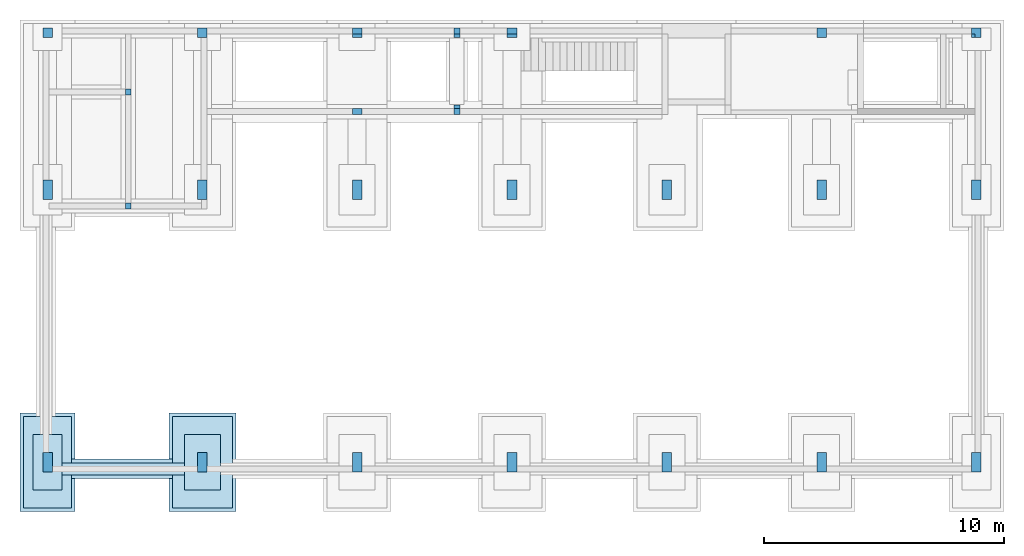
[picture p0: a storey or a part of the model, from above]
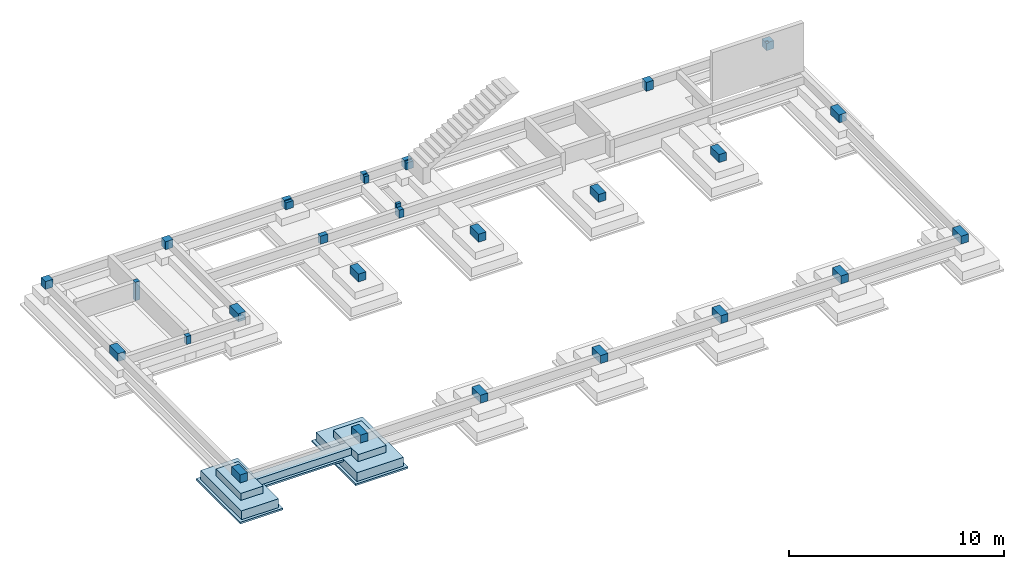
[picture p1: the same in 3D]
Properties of the parts of a building model (IFC2X3), part 1 of 2

# File
Description: ViewDefinition [CoordinationView_V2.0]
File name: Numer projektu
Time: 2022-04-22T09:22:17
Written by: The EXPRESS Data Manager Version 5.02.0100.07 : 28 Aug 2013
Made in: 22.0.2.392 - Exporter 22.0.2.392 - Zastępczy Interfejs Użytkownika 22.0.2.392
Comment: STEP Physical File produced by: The EXPRESS Data Manager Version 5.02.0100.07 : 28 Aug 2013 * Module: EDMstepFileFactory/EDMstandAlone * Creation date: Fri Apr 22 09:22:17 2022 * Host: DESKTOP-EC0AMMV * Database: C:\Users\User\AppData\Local\Temp\685c151b-a8d0-49df-8c9f-2104059c286f\b235b335-c000-40b2-a10a-5bbda26b3f6b\ifc * Database version: 5507 * Database creation date: Fri Apr 22 09:21:30 2022 * Schema: IFC2X3 * Model: DataRepository.ifc * Model creation date: Fri Apr 22 09:21:31 2022 * Header model: DataRepository.ifc_HeaderModel * Header model creation date: Fri Apr 22 09:21:31 2022 * EDMuser: sdai-user * EDMgroup: sdai-group * License ID and type: 5605 : Permanent license. Expiry date: * EDMstepFileFactory options: 020000

# IfcProject, Numer projektu
LongName: Nazwa projektu; Phase: Stan projektu

# IfcSite, Default
RefLatitude: 52, 14, 59, 999999; RefLongitude: 20, 59, 59, 999999; RefElevation: 0 cm

# IfcBuilding
Pset_BuildingCommon - NumberOfStoreys: 6

# IfcBuildingStorey: Poziom:8 mm - początek (6)
Name | LongName | Elevation (cm)
Poziom Fundament -1,15 | Poziom Fundament -1,15 | -115
Poziom 0K -0,10 | Poziom 0K -0,10 | -10
Poziom 0 A +/-0,00 | Poziom 0 A +/-0,00 | 3.3857e-11
Poziom Antresola +2,90 | Poziom Antresola +2,90 | 290
Poziom 1K +5,45 | Poziom 1K +5,45 | 545
Poziom 2K +9,70 | Poziom 2K +9,70 | 970

# IfcBeam: Beton-belka prostokątna:BELKA 190x25, Beton-belka prostokątna:BELKA 190x25:542715
In: Poziom 2K +9,70
Type - Pset_BeamCommon - LoadBearing: yes; IsExternal: no
Material: _Beton C30/37
Pset_BeamCommon - Slope: 0 deg; Reference: BELKA 190x25; Span: 854.762 cm
Pset_QuantityTakeOff - Reference: BELKA 190x25; sets with these values: 2

# IfcBeam: Beton-belka prostokątna:BELKA 21x34, Beton-belka prostokątna:BELKA 21x34:641071
In: Poziom 1K +5,45
Type - Pset_BeamCommon - LoadBearing: yes; IsExternal: no
Material: _Beton C30/37
Pset_BeamCommon - Slope: 0 deg; Reference: BELKA 21x34; Span: 297 cm
Pset_QuantityTakeOff - Reference: BELKA 21x34; sets with these values: 2

# IfcBeam: Beton-belka prostokątna:BELKA 25x40 (2)
In: Poziom 1K +5,45
Type - Pset_BeamCommon - LoadBearing: yes; IsExternal: no
Material: _Beton C30/37
Pset_BeamCommon - Slope: 0 deg; Reference: BELKA 25x40; Span: 622.5 cm
Pset_QuantityTakeOff - Reference: BELKA 25x40; sets with these values: 2
Name (Beton-belka prostokątna:BELKA 25x40:...)
481778
486543

# IfcBeam: Beton-belka prostokątna:BELKA 40x30 (2)
In: Poziom 1K +5,45
Type - PredefinedType: BEAM; Material: _Beton C30/37
Type - Pset_BeamCommon - LoadBearing: yes; IsExternal: no
Pset_BeamCommon - Slope: 0 deg; Reference: BELKA 40x30
Pset_QuantityTakeOff - Reference: BELKA 40x30; sets with these values: 2
Name (Beton-belka prostokątna:BELKA 40x30:...) | Span (cm)
435028 | 1850
448956 | 665

# IfcBeam: Beton-belka prostokątna:BELKA 40x30 (13)
In: Poziom 1K +5,45
Type - Pset_BeamCommon - LoadBearing: yes; IsExternal: no
Material: _Beton C30/37
Pset_BeamCommon - Slope: 0 deg; Reference: BELKA 40x30
Pset_QuantityTakeOff - Reference: BELKA 40x30; sets with these values: 2
Name (Beton-belka prostokątna:BELKA 40x30:...) | Span (cm)
434826 | 350
447698 | 305
447766 | 1195
448347 | 625
448529 | 645
448852 | 427.5
449135 | 625
596459 | 605
597098 | 605
597211 | 605
597310 | 605
597330 | 605
597412 | 800

# IfcBeam: Beton-belka prostokątna:BELKA 40x45 (2)
In: Poziom 0K -0,10
Type - Pset_BeamCommon - LoadBearing: yes; IsExternal: no
Material: _Beton C30/37
Pset_BeamCommon - Slope: 0 deg; Reference: BELKA 40x45
Pset_QuantityTakeOff - Reference: BELKA 40x45; sets with these values: 2
Name (Beton-belka prostokątna:BELKA 40x45:...) | Span (cm)
433060 | 123.77
660178 | 531.23

# IfcBeam: Beton-belka prostokątna:BELKA ŻELBETOWA 10x25 (3)
In: Poziom Antresola +2,90
Type - Pset_BeamCommon - LoadBearing: yes; IsExternal: no
Material: _Beton C30/37
Pset_BeamCommon - Slope: 0 deg; Reference: BELKA ŻELBETOWA 10x25
Pset_QuantityTakeOff - Reference: BELKA ŻELBETOWA 10x25; sets with these values: 2
Name (Beton-belka prostokątna:BELKA ŻELBETOWA 10x25:...) | Span (cm)
526152 | 331
534554 | 463.5
534562 | 331

# IfcBeam: Beton-belka prostokątna:BELKA ŻELBETOWA 35x25, Beton-belka prostokątna:BELKA ŻELBETOWA 35x25:540405
In: Poziom Antresola +2,90
Type - Pset_BeamCommon - LoadBearing: yes; IsExternal: no
Material: _Beton C30/37
Pset_BeamCommon - Slope: 0 deg; Reference: BELKA ŻELBETOWA 35x25; Span: 242.456 cm
Pset_QuantityTakeOff - Reference: BELKA ŻELBETOWA 35x25; sets with these values: 2

# IfcBeam: Beton-belka prostokątna:Belka żelbetowa 40x155cm (9)
In: Poziom 0K -0,10
Type - Pset_BeamCommon - LoadBearing: yes; IsExternal: no
Material: _Beton C30/37
Pset_BeamCommon - Slope: 0 deg; Reference: Belka żelbetowa 40x155cm
Pset_QuantityTakeOff - Reference: Belka żelbetowa 40x155cm; sets with these values: 2
Name (Beton-belka prostokątna:Belka żelbetowa 40x155cm:...) | Span (cm)
432161 | 1215
432658 | 1113.75
437235 | 655
438517 | 625
439012 | 645
439243 | 645
439613 | 645
439765 | 645
439812 | 625

# IfcBeam: Beton-belka prostokątna:Belka żelbetowa 40x60cm (6)
In: Poziom 0K -0,10
Type - Pset_BeamCommon - LoadBearing: yes; IsExternal: no
Material: _Beton C30/37
Pset_BeamCommon - Slope: 0 deg; Reference: Belka żelbetowa 40x60cm
Pset_QuantityTakeOff - Reference: Belka żelbetowa 40x60cm; sets with these values: 2
Name (Beton-belka prostokątna:Belka żelbetowa 40x60cm:...) | Span (cm)
481795 | 605
481805 | 606
481807 | 606
481809 | 606
481814 | 605
481832 | 605

# IfcBeam: Beton-belka prostokątna:Belka żelbetowa 40x65 cm (5)
In: Poziom 0K -0,10
Type - PredefinedType: BEAM; Material: _Beton, C25/30
Type - Pset_BeamCommon - LoadBearing: yes; IsExternal: no
Pset_BeamCommon - Slope: 0 deg; Reference: Belka żelbetowa 40x65 cm
Pset_QuantityTakeOff - Reference: Belka żelbetowa 40x65 cm; sets with these values: 2
Name (Beton-belka prostokątna:Belka żelbetowa 40x65 cm:...) | Span (cm)
422655 | 1175
432189 | 1175
432206 | 1175
432730 | 1176
481820 | 1176

# IfcBeam: Beton-belka prostokątna:wieniec 10x15 (8)
In: Poziom 2K +9,70
Type - Pset_BeamCommon - LoadBearing: yes; IsExternal: no
Material: _Beton C30/37
Pset_BeamCommon - Slope: 0 deg; Reference: wieniec 10x15
Pset_QuantityTakeOff - Reference: wieniec 10x15; sets with these values: 2
Name (Beton-belka prostokątna:wieniec 10x15:...) | Span (cm)
623789 | 80.0001
623798 | 80.0001
623804 | 250
623812 | 250
635637 | 115
635639 | 120.002
635653 | 115
635659 | 120.002

# IfcBeam: Beton-belka prostokątna:wieniec 25x25 (18)
Type - PredefinedType: BEAM; Material: _Beton C30/37
Type - Pset_BeamCommon - LoadBearing: yes; IsExternal: no
Pset_BeamCommon - Slope: 0 deg; Reference: wieniec 25x25
Pset_QuantityTakeOff - Reference: wieniec 25x25; sets with these values: 2
Name (Beton-belka prostokątna:wieniec 25x25:...) | In | Span (cm)
443020 | Poziom 0K -0,10 | 1024
443519 | Poziom 0K -0,10 | 330
443610 | Poziom 0K -0,10 | 605
443694 | Poziom 0K -0,10 | 605
443745 | Poziom 0K -0,10 | 605
443802 | Poziom 0K -0,10 | 1041.51
451564 | Poziom 1K +5,45 | 1001.8
452412 | Poziom 1K +5,45 | 605
452460 | Poziom 1K +5,45 | 605
452469 | Poziom 1K +5,45 | 605
452478 | Poziom 1K +5,45 | 605
452495 | Poziom 1K +5,45 | 605
452915 | Poziom 1K +5,45 | 1001.8
564734 | Poziom 0 A +/-0,00 | 329
565840 | Poziom 0 A +/-0,00 | 6
565847 | Poziom Antresola +2,90 | 2.5
565852 | Poziom 0 A +/-0,00 | 273
601474 | Poziom 1K +5,45 | 273

# IfcBeam: C:C160 (6)
In: Poziom Antresola +2,90
Type - Pset_BeamCommon - LoadBearing: yes; IsExternal: no
Material: Stal konstrukcyjna - S235
Pset_BeamCommon - Slope: 0 deg; Reference: C160
Pset_QuantityTakeOff - Reference: C160; sets with these values: 2
Name (C:C160:...) | Span (cm)
565581 | 285.5
565635 | 632.87
565638 | 1275.61
567058 | 427.36
567066 | 291.16
574626 | 167.49

# IfcBeam: C:C200 (6)
Type - Pset_BeamCommon - LoadBearing: yes; IsExternal: no
Material: Stal konstrukcyjna - S235
Pset_BeamCommon - Reference: C200
Pset_QuantityTakeOff - Reference: C200; sets with these values: 2
Name (C:C200:...) | In | Slope (deg) | Span (cm)
692104 | Poziom 2K +9,70 | 0 | 262
692492 | Poziom 2K +9,70 | 0 | 268.31
696956 | Poziom 1K +5,45 | 0 | 229.99
697291 | Poziom 1K +5,45 | 0 | 229.99
698559 | Poziom 1K +5,45 | 31.257 | 462.73
702117 | Poziom 1K +5,45 | 31.257 | 462.73

# IfcBeam: C:C260 (6)
In: Poziom Antresola +2,90
Type - Pset_BeamCommon - LoadBearing: yes; IsExternal: no
Material: Stal konstrukcyjna - S235
Pset_BeamCommon - Slope: 0 deg; Reference: C260
Pset_QuantityTakeOff - Reference: C260; sets with these values: 2
Name (C:C260:...) | Span (cm)
559119 | 606.81
559125 | 285.41
559130 | 276
565572 | 632.87
567040 | 605.29
567049 | 250

# IfcBeam: C:C320, C:C320:586744
In: Poziom Antresola +2,90
Type - Pset_BeamCommon - LoadBearing: yes; IsExternal: no
Material: Stal konstrukcyjna - S235
Pset_BeamCommon - Slope: 0 deg; Reference: C320; Span: 590 cm
Pset_QuantityTakeOff - Reference: C320; sets with these values: 2

# IfcBeam: HE-B:HEB160 (8)
In: Poziom 2K +9,70
Type - Pset_BeamCommon - LoadBearing: yes; IsExternal: no
Material: Stal konstrukcyjna - S235
Pset_BeamCommon - Slope: 0 deg; Reference: HEB160
Pset_QuantityTakeOff - Reference: HEB160; sets with these values: 2
Name (HE-B:HEB160:...) | Span (cm)
684759 | 204
684765 | 204
689017 | 204
689019 | 204
689044 | 204
689046 | 204
691939 | 135
691985 | 135

# IfcBeam: IN:IN300 (3)
In: Poziom 0 A +/-0,00
Type - Pset_BeamCommon - LoadBearing: yes; IsExternal: no
Material: Stal konstrukcyjna - S235
Pset_BeamCommon - Slope: 0 deg; Reference: IN300
Pset_QuantityTakeOff - Reference: IN300; sets with these values: 2
Name (IN:IN300:...) | Span (cm)
608245 | 1358
608252 | 1358
611604 | 1360

# IfcBeam: IPE:IPE100 (13)
In: Poziom Antresola +2,90
Type - Pset_BeamCommon - LoadBearing: yes; IsExternal: no
Material: Stal konstrukcyjna - S235
Pset_BeamCommon - Slope: 0 deg; Reference: IPE100
Pset_QuantityTakeOff - Reference: IPE100; sets with these values: 2
Name (IPE:IPE100:...) | Span (cm)
573239 | 90
573250 | 90
573257 | 90
573260 | 90
573275 | 90
573342 | 76
573538 | 76
573555 | 76
573559 | 76
573601 | 110
573827 | 110
573844 | 110
573891 | 76

# IfcBeam: IPE:IPE140 (4)
In: Poziom Antresola +2,90
Type - Pset_BeamCommon - LoadBearing: yes; IsExternal: no
Material: Stal konstrukcyjna - S235
Pset_BeamCommon - Slope: 0 deg; Reference: IPE140
Pset_QuantityTakeOff - Reference: IPE140; sets with these values: 2
Name (IPE:IPE140:...) | Span (cm)
575010 | 89.5
575096 | 93.49
575265 | 95.74
575303 | 95.74

# IfcBeam: IPE:IPE160 (6)
In: Poziom Antresola +2,90
Type - Pset_BeamCommon - LoadBearing: yes; IsExternal: no
Material: Stal konstrukcyjna - S235
Pset_BeamCommon - Slope: 0 deg; Reference: IPE160
Pset_QuantityTakeOff - Reference: IPE160; sets with these values: 2
Name (IPE:IPE160:...) | Span (cm)
565586 | 266.71
565593 | 269.45
565600 | 266.71
565606 | 259.52
565613 | 259.52
574786 | 194

# IfcBeam: Równoramienne L:L80x8 (26)
Type - Pset_BeamCommon - LoadBearing: yes; IsExternal: no
Material: Stal konstrukcyjna - S235
Pset_BeamCommon - Reference: L80x8
Pset_QuantityTakeOff - Reference: L80x8; sets with these values: 2
Name (Równoramienne L:L80x8:...) | In | Span (cm) | Slope (deg)
612930 | Poziom 1K +5,45 | 115.72 | 49.9154
612940 | Poziom 1K +5,45 | 115.72 | 49.9154
612947 | Poziom 1K +5,45 | 115.72 | 49.9154
612949 | Poziom 1K +5,45 | 115.72 | 49.9154
618599 | Poziom 0K -0,10 | 36 | 0
618607 | Poziom 1K +5,45 | 115.72 | 49.9154
621075 | Poziom 1K +5,45 | 115.72 | 49.9154
621087 | Poziom 1K +5,45 | 115.72 | 49.9154
621093 | Poziom 1K +5,45 | 115.72 | 49.9154
621099 | Poziom 1K +5,45 | 115.72 | 49.9154
621105 | Poziom 1K +5,45 | 115.72 | 49.9154
621111 | Poziom 1K +5,45 | 115.72 | 49.9154
621117 | Poziom 1K +5,45 | 115.72 | 49.9154
621123 | Poziom 1K +5,45 | 115.72 | 49.9154
621129 | Poziom 1K +5,45 | 115.72 | 49.9154
621135 | Poziom 1K +5,45 | 115.72 | 49.9154
621138 | Poziom 1K +5,45 | 115.72 | 49.9154
621150 | Poziom 1K +5,45 | 115.72 | 49.9154
621156 | Poziom 1K +5,45 | 115.72 | 49.9154
623098 | Poziom 0 A +/-0,00 | 1358 | 0
623288 | Poziom 0 A +/-0,00 | 1358 | 0
623305 | Poziom 0 A +/-0,00 | 1358 | 0
623544 | Poziom 0 A +/-0,00 | 1358 | 0
623557 | Poziom 0 A +/-0,00 | 1358 | 0
623572 | Poziom 0 A +/-0,00 | 1358 | 0
627711 | Poziom 1K +5,45 | 41.59 | 49.9215

# IfcBeam: STAL RK - Ksztaltowniki zamkniete kwadratowe:RK150x6 (29)
Type - Pset_BeamCommon - LoadBearing: yes; IsExternal: no
Material: Stal konstrukcyjna - S235
Pset_BeamCommon - Slope: 0 deg; Reference: RK150x6
Pset_QuantityTakeOff - Reference: RK150x6; sets with these values: 2
Name (STAL RK - Ksztaltowniki zamkniete kwadratowe:RK150x6:...) | In | Span (cm)
678637 | Poziom 2K +9,70 | 230
679442 | Poziom 2K +9,70 | 230
679449 | Poziom 2K +9,70 | 230
679455 | Poziom 1K +5,45 | 230
679466 | Poziom 2K +9,70 | 380
680834 | Poziom 2K +9,70 | 380
680838 | Poziom 2K +9,70 | 380
680842 | Poziom 1K +5,45 | 380
680863 | Poziom 2K +9,70 | 389.9
681220 | Poziom 2K +9,70 | 389.9
681235 | Poziom 2K +9,70 | 389.9
681250 | Poziom 1K +5,45 | 389.9
681398 | Poziom 2K +9,70 | 10.5
681550 | Poziom 2K +9,70 | 10.5
681567 | Poziom 2K +9,70 | 10.5
681584 | Poziom 1K +5,45 | 10.5
682621 | Poziom 2K +9,70 | 10.5
682625 | Poziom 2K +9,70 | 10.5
682638 | Poziom 2K +9,70 | 163.7
682654 | Poziom 2K +9,70 | 163.7
682660 | Poziom 2K +9,70 | 163.7
682666 | Poziom 2K +9,70 | 587
682828 | Poziom 2K +9,70 | 163.7
682873 | Poziom 2K +9,70 | 163.7
682889 | Poziom 2K +9,70 | 163.7
682947 | Poziom 2K +9,70 | 163.7
683577 | Poziom 2K +9,70 | 389.9
690285 | Poziom 2K +9,70 | 231.5
691914 | Poziom 2K +9,70 | 146.4

# IfcBuildingElementProxy: Dłutownica do metalu:Dłutownica do metalu, Dłutownica do metalu:Dłutownica do metalu:716176
In: Poziom 0 A +/-0,00
Type - Material: Urządzenia
Pset_BuildingElementProxyCommon - Reference: Dłutownica do metalu; sets with these values: 2
Pset_ProvisionForVoid - Width: 155 cm; Height: 80 cm; Depth: 155 cm

# IfcBuildingElementProxy: Prasa hydrauliczna:Prasa hydrauliczna, Prasa hydrauliczna:Prasa hydrauliczna:716599
In: Poziom 0 A +/-0,00
Type - Material: Urządzenia
Pset_BuildingElementProxyCommon - Reference: Prasa hydrauliczna; sets with these values: 2
Pset_ProvisionForVoid - Width: 202.5 cm; Height: 80 cm; Depth: 202.5 cm

# IfcColumn: Beton-słup prostokątny:S3, Beton-słup prostokątny:S3:414509
In: Poziom Fundament -1,15
Type - PredefinedType: COLUMN; Material: <Unnamed>
Type - Pset_ColumnCommon - LoadBearing: yes; IsExternal: no
Pset_ColumnCommon - Reference: S3
Pset_QuantityTakeOff - Reference: S3; sets with these values: 2

# IfcColumn: Beton-słup prostokątny:Słup 24 x 24 cm (2)
In: Poziom Fundament -1,15
Type - PredefinedType: COLUMN; Material: _Beton, C25/30
Type - Pset_ColumnCommon - LoadBearing: yes; IsExternal: no
Pset_ColumnCommon - Reference: Słup 24 x 24 cm
Pset_QuantityTakeOff - Reference: Słup 24 x 24 cm; sets with these values: 2
Name (Beton-słup prostokątny:Słup 24 x 24 cm:...)
413514
413523

# IfcColumn: Beton-słup prostokątny:Słup 25 x 25 cm (2)
In: Poziom 1K +5,45
Type - PredefinedType: COLUMN; Material: _Beton, C25/30
Type - Pset_ColumnCommon - LoadBearing: yes; IsExternal: no
Pset_ColumnCommon - Reference: Słup 25 x 25 cm
Pset_QuantityTakeOff - Reference: Słup 25 x 25 cm; sets with these values: 2
Name (Beton-słup prostokątny:Słup 25 x 25 cm:...)
486550
555746 | Pset_ColumnCommon - Slope: 0 deg

# IfcColumn: Beton-słup prostokątny:Słup 25 x 40 cm (5)
Type - PredefinedType: COLUMN; Material: _Beton, C25/30
Type - Pset_ColumnCommon - LoadBearing: yes; IsExternal: no
Pset_ColumnCommon - Reference: Słup 25 x 40 cm
Pset_QuantityTakeOff - Reference: Słup 25 x 40 cm; sets with these values: 2
Name (Beton-słup prostokątny:Słup 25 x 40 cm:...) | In
409615 | Poziom Fundament -1,15
409624 | Poziom Fundament -1,15
409630 | Poziom Fundament -1,15
449383 | Poziom 0K -0,10 | Pset_ColumnCommon - Slope: 0 deg
538220 | Poziom Antresola +2,90 | Pset_ColumnCommon - Slope: 0 deg

# IfcColumn: Beton-słup prostokątny:Słup 40 x 80 cm (42)
Type - PredefinedType: COLUMN; Material: _Beton, C25/30
Type - Pset_ColumnCommon - LoadBearing: yes; IsExternal: no
Pset_ColumnCommon - Reference: Słup 40 x 80 cm
Pset_QuantityTakeOff - Reference: Słup 40 x 80 cm; sets with these values: 2
Name (Beton-słup prostokątny:Słup 40 x 80 cm:...) | In
409481 | Poziom Fundament -1,15
409490 | Poziom Fundament -1,15
409496 | Poziom Fundament -1,15
409502 | Poziom Fundament -1,15
409508 | Poziom Fundament -1,15
409514 | Poziom Fundament -1,15
409520 | Poziom Fundament -1,15
409543 | Poziom Fundament -1,15
409549 | Poziom Fundament -1,15
409555 | Poziom Fundament -1,15
409561 | Poziom Fundament -1,15
409567 | Poziom Fundament -1,15
409573 | Poziom Fundament -1,15
409579 | Poziom Fundament -1,15
416069 | Poziom 0K -0,10
416393 | Poziom 0K -0,10
416405 | Poziom 0K -0,10
416419 | Poziom 0K -0,10
416433 | Poziom 0K -0,10
416447 | Poziom 0K -0,10
416461 | Poziom 0K -0,10 | Pset_ColumnCommon - Slope: 0 deg
416513 | Poziom 0K -0,10
416529 | Poziom 0K -0,10
416545 | Poziom 0K -0,10
416557 | Poziom 0K -0,10
416575 | Poziom 0K -0,10
416587 | Poziom 0K -0,10
416599 | Poziom 0K -0,10
418835 | Poziom 1K +5,45 | Pset_ColumnCommon - Slope: 0 deg
418837 | Poziom 1K +5,45
418839 | Poziom 1K +5,45 | Pset_ColumnCommon - Slope: 0 deg
418841 | Poziom 1K +5,45 | Pset_ColumnCommon - Slope: 0 deg
418843 | Poziom 1K +5,45
418845 | Poziom 1K +5,45
418847 | Poziom 1K +5,45 | Pset_ColumnCommon - Slope: 0 deg
419149 | Poziom 1K +5,45 | Pset_ColumnCommon - Slope: 0 deg
419151 | Poziom 1K +5,45 | Pset_ColumnCommon - Slope: 0 deg
419153 | Poziom 1K +5,45 | Pset_ColumnCommon - Slope: 0 deg
419155 | Poziom 1K +5,45 | Pset_ColumnCommon - Slope: 0 deg
419157 | Poziom 1K +5,45 | Pset_ColumnCommon - Slope: 0 deg
419159 | Poziom 1K +5,45 | Pset_ColumnCommon - Slope: 0 deg
419161 | Poziom 1K +5,45 | Pset_ColumnCommon - Slope: 0 deg

# IfcColumn: Beton-słup prostokątny:Słup żelbetowy 40x40cm (24)
Type - PredefinedType: COLUMN; Material: _Beton, C25/30
Type - Pset_ColumnCommon - LoadBearing: yes; IsExternal: no
Pset_ColumnCommon - Reference: Słup żelbetowy 40x40cm
Pset_QuantityTakeOff - Reference: Słup żelbetowy 40x40cm; sets with these values: 2
Name (Beton-słup prostokątny:Słup żelbetowy 40x40cm:...) | In
401556 | Poziom Fundament -1,15
409585 | Poziom Fundament -1,15
409591 | Poziom Fundament -1,15
409597 | Poziom Fundament -1,15
409603 | Poziom Fundament -1,15
409609 | Poziom Fundament -1,15
415508 | Poziom Fundament -1,15
415515 | Poziom Fundament -1,15
415654 | Poziom 0K -0,10
415978 | Poziom 0K -0,10
415992 | Poziom 0K -0,10
416008 | Poziom 0K -0,10
416024 | Poziom 0K -0,10
418922 | Poziom 1K +5,45 | Pset_ColumnCommon - Slope: 0 deg
418924 | Poziom 1K +5,45 | Pset_ColumnCommon - Slope: 0 deg
418926 | Poziom 1K +5,45 | Pset_ColumnCommon - Slope: 0 deg
418928 | Poziom 1K +5,45 | Pset_ColumnCommon - Slope: 0 deg
418930 | Poziom 1K +5,45
418974 | Poziom 1K +5,45 | Pset_ColumnCommon - Slope: 0 deg
484284 | Poziom 0 A +/-0,00
496551 | Poziom Antresola +2,90 | Pset_ColumnCommon - Slope: 0 deg
496959 | Poziom Antresola +2,90
527963 | Poziom Antresola +2,90
527965 | Poziom Antresola +2,90

# IfcColumn: STAL RK - Ksztaltowniki zamkniete kwadratowe_Słup:RK150x6 (9)
Type - PredefinedType: COLUMN; Material: Metal — stal — Stal
Type - Pset_ColumnCommon - LoadBearing: yes; IsExternal: no
Pset_ColumnCommon - Reference: RK150x6
Pset_QuantityTakeOff - Reference: RK150x6; sets with these values: 2
Name (STAL RK - Ksztaltowniki zamkniete kwadratowe_Słup:RK150x6:...) | In
670864 | Poziom 1K +5,45
671949 | Poziom 1K +5,45
671972 | Poziom 1K +5,45
672210 | Poziom 1K +5,45
672255 | Poziom 1K +5,45
672369 | Poziom 1K +5,45
682645 | Poziom 1K +5,45
690274 | Poziom 2K +9,70
690281 | Poziom 2K +9,70

# IfcColumn: STAL RK - Ksztaltowniki zamkniete kwadratowe_Słup:RK150x6, STAL RK - Ksztaltowniki zamkniete kwadratowe_Słup:RK150x6:672487
In: Poziom 1K +5,45
Type - PredefinedType: COLUMN; Material: Stal konstrukcyjna - S235
Type - Pset_ColumnCommon - LoadBearing: yes; IsExternal: no
Pset_ColumnCommon - Reference: RK150x6
Pset_QuantityTakeOff - Reference: RK150x6; sets with these values: 2

# IfcColumn: Słup C:C160, Słup C:C160:594198
In: Poziom 1K +5,45
Type - PredefinedType: COLUMN; Material: Stal konstrukcyjna - S235
Type - Pset_ColumnCommon - LoadBearing: yes; IsExternal: no
Pset_ColumnCommon - Reference: C160
Pset_QuantityTakeOff - Reference: C160; sets with these values: 2

# IfcColumn: Słup HE-A:HEA160 (10)
Type - PredefinedType: COLUMN; Material: Metal — stal — Stal
Type - Pset_ColumnCommon - LoadBearing: yes; IsExternal: no
Pset_ColumnCommon - Reference: HEA160
Pset_QuantityTakeOff - Reference: HEA160; sets with these values: 2
Name (Słup HE-A:HEA160:...) | In
684783 | Poziom 1K +5,45
690233 | Poziom 1K +5,45
690239 | Poziom 1K +5,45
690241 | Poziom 1K +5,45
690251 | Poziom 1K +5,45
690253 | Poziom 1K +5,45
691922 | Poziom 2K +9,70
691935 | Poziom 2K +9,70
691981 | Poziom 2K +9,70
691983 | Poziom 2K +9,70

# IfcColumn: Słup IN:IN300 (9)
In: Poziom 0 A +/-0,00
Type - PredefinedType: COLUMN; Material: Stal konstrukcyjna - S235
Type - Pset_ColumnCommon - LoadBearing: yes; IsExternal: no
Pset_ColumnCommon - Reference: IN300
Pset_QuantityTakeOff - Reference: IN300; sets with these values: 2
Name (Słup IN:IN300:...)
632740
635753
635760
635767
635773
635780
635788
635794
635804

# IfcCurtainWall: Ściana osłonowa:S1.4, Ściana osłonowa:S1.4:653767
In: Poziom 1K +5,45
Type - Pset_CurtainWallCommon - IsExternal: yes
Pset_CurtainWallCommon - Reference: S1.4
Pset_QuantityTakeOff - Reference: S1.4

# IfcCurtainWall: Ściana osłonowa:SO1 (16)
Type - Pset_CurtainWallCommon - IsExternal: yes
Pset_CurtainWallCommon - Reference: SO1
Pset_QuantityTakeOff - Reference: SO1
Name (Ściana osłonowa:SO1:...) | In
540286 | Poziom 1K +5,45
557872 | Poziom 1K +5,45
585415 | Poziom 0 A +/-0,00
586807 | Poziom 0 A +/-0,00
586843 | Poziom 0 A +/-0,00
588400 | Poziom 0 A +/-0,00
591702 | Poziom 0 A +/-0,00
597959 | Poziom 1K +5,45
599544 | Poziom 1K +5,45
599579 | Poziom 1K +5,45
599614 | Poziom 1K +5,45
599649 | Poziom 1K +5,45
599787 | Poziom 1K +5,45
601892 | Poziom 1K +5,45
627485 | Poziom 0 A +/-0,00
643511 | Poziom 0 A +/-0,00

# IfcCurtainWall: Ściana osłonowa:SO2 (2)
Type - Pset_CurtainWallCommon - IsExternal: yes
Pset_CurtainWallCommon - Reference: SO2
Pset_QuantityTakeOff - Reference: SO2
Name (Ściana osłonowa:SO2:...) | In
602537 | Poziom Antresola +2,90
613172 | Poziom 0 A +/-0,00

# IfcDistributionPort (2)
Description: Flow; FlowDirection: SOURCEANDSINK; Group: Mechaniczne Powietrze nawiewane 1

# IfcFlowSegment: Kanał prostokątny:Domyślny, Kanał prostokątny:Domyślny:718157
In: Poziom Antresola +2,90
Pset_DistributionFlowElementCommon - Reference: Domyślny; sets with these values: 2
Pset_DuctSegmentTypeCommon - Length: 30.48 cm; sets with these values: 3
Group: Mechaniczne Powietrze nawiewane 1

# IfcFurnishingElement: Krzesło - zestawiane w stos:Krzesło - zestawiane w stos (10)
In: Poziom 0 A +/-0,00
Type - Material: Wiśnia, Stal, chromowana
Material: Stal, chromowana, Wiśnia
Pset_QuantityTakeOff - Reference: Krzesło - zestawiane w stos
Name (Krzesło - zestawiane w stos:Krzesło - zestawiane w stos:...)
714844
715081
715268
715558
715595
715616
715653
715654
715685
715742

# IfcFurnishingElement: Stół - prostokątny:2000 x 1250 (4)
In: Poziom 0 A +/-0,00
Type - Material: MDF biały (5)
Pset_QuantityTakeOff - Reference: 2000 x 1250
Name (Stół - prostokątny:2000 x 1250:...) | Material
715398
715485 | MDF biały
715506 | MDF biały
715527 | MDF biały

# IfcFurnishingElement: Stół - prostokątny:2000 x 750 mm (4)
In: Poziom 0 A +/-0,00
Type - Material: MDF biały (5)
Pset_QuantityTakeOff - Reference: 2000 x 750 mm
Name (Stół - prostokątny:2000 x 750 mm:...) | Material
713128
715180 | MDF biały
715326 | MDF biały
715349 | MDF biały

# IfcMember: Prostokątny szpros:50 x 175mm (86)
Type - PredefinedType: MULLION; Material: Aluminium
Type - Pset_MemberCommon - IsExternal: no
Pset_MemberCommon - Reference: 50 x 175mm
Pset_QuantityTakeOff - Reference: 50 x 175mm
Name (Prostokątny szpros:50 x 175mm:...) | In | Span (cm)
602542 | Poziom Antresola +2,90 | 56
602543 | Poziom Antresola +2,90 | 53.5
602544 | Poziom Antresola +2,90 | 125
602545 | Poziom Antresola +2,90 | 198.5
611655 | Poziom Antresola +2,90 | 121
611656 | Poziom Antresola +2,90 | 48.5
611657 | Poziom Antresola +2,90 | 125
611667 | Poziom Antresola +2,90 | 121
611668 | Poziom Antresola +2,90 | 116
611669 | Poziom Antresola +2,90 | 125
611678 | Poziom Antresola +2,90 | 121
611679 | Poziom Antresola +2,90 | 116
611680 | Poziom Antresola +2,90 | 125
611688 | Poziom Antresola +2,90 | 121
611689 | Poziom Antresola +2,90 | 116
611690 | Poziom Antresola +2,90 | 125
611696 | Poziom Antresola +2,90 | 121
611697 | Poziom Antresola +2,90 | 116
611698 | Poziom Antresola +2,90 | 125
611705 | Poziom Antresola +2,90 | 118.5
611706 | Poziom Antresola +2,90 | 116
611707 | Poziom Antresola +2,90 | 125
611716 | Poziom Antresola +2,90 | 119
611717 | Poziom Antresola +2,90 | 113.5
611718 | Poziom Antresola +2,90 | 125
611727 | Poziom Antresola +2,90 | 51
611728 | Poziom Antresola +2,90 | 114
611729 | Poziom Antresola +2,90 | 125
611894 | Poziom Antresola +2,90 | 193.5
611895 | Poziom Antresola +2,90 | 120
611896 | Poziom Antresola +2,90 | 56
611897 | Poziom Antresola +2,90 | 119
611898 | Poziom Antresola +2,90 | 118.5
611899 | Poziom Antresola +2,90 | 121
611900 | Poziom Antresola +2,90 | 121
611901 | Poziom Antresola +2,90 | 121
611902 | Poziom Antresola +2,90 | 121
611903 | Poziom Antresola +2,90 | 121
611904 | Poziom Antresola +2,90 | 56
611905 | Poziom Antresola +2,90 | 193.5
611906 | Poziom Antresola +2,90 | 193.5
611907 | Poziom Antresola +2,90 | 193.5
611908 | Poziom Antresola +2,90 | 193.5
611909 | Poziom Antresola +2,90 | 193.5
611910 | Poziom Antresola +2,90 | 193.5
611911 | Poziom Antresola +2,90 | 193.5
611912 | Poziom Antresola +2,90 | 193.5
613174 | Poziom 0 A +/-0,00 | 56
613175 | Poziom 0 A +/-0,00 | 53.5
613176 | Poziom 0 A +/-0,00 | 247.5
613177 | Poziom 0 A +/-0,00 | 127.5
613181 | Poziom 0 A +/-0,00 | 121
613182 | Poziom 0 A +/-0,00 | 48.5
613183 | Poziom 0 A +/-0,00 | 247.5
613186 | Poziom 0 A +/-0,00 | 121
613187 | Poziom 0 A +/-0,00 | 116
613188 | Poziom 0 A +/-0,00 | 247.5
613191 | Poziom 0 A +/-0,00 | 121
613192 | Poziom 0 A +/-0,00 | 118.5
613193 | Poziom 0 A +/-0,00 | 242.5
613196 | Poziom 0 A +/-0,00 | 121
613197 | Poziom 0 A +/-0,00 | 118.5
613198 | Poziom 0 A +/-0,00 | 247.5
613201 | Poziom 0 A +/-0,00 | 121
613202 | Poziom 0 A +/-0,00 | 118.5
613203 | Poziom 0 A +/-0,00 | 242.5
613206 | Poziom 0 A +/-0,00 | 118.5
613207 | Poziom 0 A +/-0,00 | 118.5
613208 | Poziom 0 A +/-0,00 | 245
613211 | Poziom 0 A +/-0,00 | 119
613212 | Poziom 0 A +/-0,00 | 116
613216 | Poziom 0 A +/-0,00 | 51
613217 | Poziom 0 A +/-0,00 | 116.5
613218 | Poziom 0 A +/-0,00 | 245
613333 | Poziom 0 A +/-0,00 | 122.5
613334 | Poziom 0 A +/-0,00 | 242.5
613335 | Poziom 0 A +/-0,00 | 121
613336 | Poziom 0 A +/-0,00 | 120
613337 | Poziom 0 A +/-0,00 | 120
613338 | Poziom 0 A +/-0,00 | 120
613339 | Poziom 0 A +/-0,00 | 122.5
613340 | Poziom 0 A +/-0,00 | 122.5
613341 | Poziom 0 A +/-0,00 | 122.5
613342 | Poziom 0 A +/-0,00 | 122.5
613343 | Poziom 0 A +/-0,00 | 122.5
613373 | Poziom 0 A +/-0,00 | 121.5

# IfcMember: Prostokątny szpros:50 x 80mm (234)
Type - PredefinedType: MULLION; Material: Aluminium
Type - Pset_MemberCommon - IsExternal: no
Pset_MemberCommon - Reference: 50 x 80mm
Pset_QuantityTakeOff - Reference: 50 x 80mm
Name (Prostokątny szpros:50 x 80mm:...) | In | Span (cm)
540302 | Poziom 1K +5,45 | 118.5
540307 | Poziom 1K +5,45 | 118.5
540312 | Poziom 1K +5,45 | 285
540314 | Poziom 1K +5,45 | 285
557855 | Poziom 1K +5,45 | 118.5
557856 | Poziom 1K +5,45 | 116
557857 | Poziom 1K +5,45 | 285
557864 | Poziom 1K +5,45 | 55.5001
557865 | Poziom 1K +5,45 | 116
557866 | Poziom 1K +5,45 | 285
557869 | Poziom 1K +5,45 | 116
557870 | Poziom 1K +5,45 | 118.5
557871 | Poziom 1K +5,45 | 285
557902 | Poziom 1K +5,45 | 116
557903 | Poziom 1K +5,45 | 55.5001
557904 | Poziom 1K +5,45 | 285
584424 | Poziom 1K +5,45 | 55.5001
584425 | Poziom 1K +5,45 | 55.5001
584426 | Poziom 1K +5,45 | 285
557874 | Poziom 1K +5,45 | 116
557875 | Poziom 1K +5,45 | 109.5
557876 | Poziom 1K +5,45 | 285
557877 | Poziom 1K +5,45 | 285
557881 | Poziom 1K +5,45 | 109.5
557882 | Poziom 1K +5,45 | 116
557883 | Poziom 1K +5,45 | 285
585421 | Poziom 0 A +/-0,00 | 113.5
585422 | Poziom 0 A +/-0,00 | 113.5
585423 | Poziom 0 A +/-0,00 | 275
585424 | Poziom 0 A +/-0,00 | 275
585724 | Poziom 0 A +/-0,00 | 113.5
585725 | Poziom 0 A +/-0,00 | 116.002
585726 | Poziom 0 A +/-0,00 | 275
586259 | Poziom 0 A +/-0,00 | 116.002
586260 | Poziom 0 A +/-0,00 | 116.002
586261 | Poziom 0 A +/-0,00 | 275
586433 | Poziom 0 A +/-0,00 | 116.002
586434 | Poziom 0 A +/-0,00 | 116.002
586435 | Poziom 0 A +/-0,00 | 275
586680 | Poziom 0 A +/-0,00 | 116.002
586681 | Poziom 0 A +/-0,00 | 113.5
586682 | Poziom 0 A +/-0,00 | 275
586809 | Poziom 0 A +/-0,00 | 113.5
586810 | Poziom 0 A +/-0,00 | 113.5
586811 | Poziom 0 A +/-0,00 | 275
586812 | Poziom 0 A +/-0,00 | 275
586815 | Poziom 0 A +/-0,00 | 113.5
586816 | Poziom 0 A +/-0,00 | 116.002
586817 | Poziom 0 A +/-0,00 | 275
586820 | Poziom 0 A +/-0,00 | 116.002
586821 | Poziom 0 A +/-0,00 | 116.002
586822 | Poziom 0 A +/-0,00 | 275
586825 | Poziom 0 A +/-0,00 | 116.002
586826 | Poziom 0 A +/-0,00 | 116.002
586827 | Poziom 0 A +/-0,00 | 275
586830 | Poziom 0 A +/-0,00 | 116.002
586831 | Poziom 0 A +/-0,00 | 113.5
586832 | Poziom 0 A +/-0,00 | 275
586845 | Poziom 0 A +/-0,00 | 113.5
586846 | Poziom 0 A +/-0,00 | 113.5
586847 | Poziom 0 A +/-0,00 | 275
586848 | Poziom 0 A +/-0,00 | 275
586851 | Poziom 0 A +/-0,00 | 113.5
586852 | Poziom 0 A +/-0,00 | 116.002
586853 | Poziom 0 A +/-0,00 | 275
586856 | Poziom 0 A +/-0,00 | 116.002
586857 | Poziom 0 A +/-0,00 | 116.002
586858 | Poziom 0 A +/-0,00 | 275
586861 | Poziom 0 A +/-0,00 | 116.002
586862 | Poziom 0 A +/-0,00 | 116.002
586863 | Poziom 0 A +/-0,00 | 275
586866 | Poziom 0 A +/-0,00 | 116.002
586867 | Poziom 0 A +/-0,00 | 113.5
586868 | Poziom 0 A +/-0,00 | 275
588405 | Poziom 0 A +/-0,00 | 118.5
588406 | Poziom 0 A +/-0,00 | 118.5
588407 | Poziom 0 A +/-0,00 | 275
588408 | Poziom 0 A +/-0,00 | 275
589707 | Poziom 0 A +/-0,00 | 118.5
589708 | Poziom 0 A +/-0,00 | 116.002
589709 | Poziom 0 A +/-0,00 | 275
589939 | Poziom 0 A +/-0,00 | 116.002
589940 | Poziom 0 A +/-0,00 | 116.002
589941 | Poziom 0 A +/-0,00 | 275
590135 | Poziom 0 A +/-0,00 | 116.002
590136 | Poziom 0 A +/-0,00 | 116.002
590137 | Poziom 0 A +/-0,00 | 275
590310 | Poziom 0 A +/-0,00 | 116.002
590311 | Poziom 0 A +/-0,00 | 118.5
590312 | Poziom 0 A +/-0,00 | 275
591707 | Poziom 0 A +/-0,00 | 123.499
591708 | Poziom 0 A +/-0,00 | 118.5
591710 | Poziom 0 A +/-0,00 | 275
595279 | Poziom 0 A +/-0,00 | 118.5
595280 | Poziom 0 A +/-0,00 | 116.002
595281 | Poziom 0 A +/-0,00 | 275
595290 | Poziom 0 A +/-0,00 | 116.002
595291 | Poziom 0 A +/-0,00 | 116.002
595292 | Poziom 0 A +/-0,00 | 275
595301 | Poziom 0 A +/-0,00 | 116.002
595302 | Poziom 0 A +/-0,00 | 116.002
595303 | Poziom 0 A +/-0,00 | 275
595312 | Poziom 0 A +/-0,00 | 116.002
595313 | Poziom 0 A +/-0,00 | 116.002
595314 | Poziom 0 A +/-0,00 | 275
595326 | Poziom 0 A +/-0,00 | 116.002
595327 | Poziom 0 A +/-0,00 | 123.499
595328 | Poziom 0 A +/-0,00 | 275
597964 | Poziom 1K +5,45 | 113.5
597965 | Poziom 1K +5,45 | 113.5
597966 | Poziom 1K +5,45 | 285
597967 | Poziom 1K +5,45 | 285
598366 | Poziom 1K +5,45 | 113.5
598367 | Poziom 1K +5,45 | 118.5
598368 | Poziom 1K +5,45 | 285
598508 | Poziom 1K +5,45 | 118.5
598509 | Poziom 1K +5,45 | 113.5
598510 | Poziom 1K +5,45 | 285
598591 | Poziom 1K +5,45 | 113.5
598592 | Poziom 1K +5,45 | 116.002
598593 | Poziom 1K +5,45 | 285
598664 | Poziom 1K +5,45 | 116.002
598665 | Poziom 1K +5,45 | 113.5
598666 | Poziom 1K +5,45 | 285
599547 | Poziom 1K +5,45 | 113.5
599548 | Poziom 1K +5,45 | 113.5
599549 | Poziom 1K +5,45 | 285
599550 | Poziom 1K +5,45 | 285
599553 | Poziom 1K +5,45 | 113.5
599554 | Poziom 1K +5,45 | 118.5
599555 | Poziom 1K +5,45 | 285
599558 | Poziom 1K +5,45 | 118.5
599559 | Poziom 1K +5,45 | 113.5
599560 | Poziom 1K +5,45 | 285
599563 | Poziom 1K +5,45 | 113.5
599564 | Poziom 1K +5,45 | 116.002
599565 | Poziom 1K +5,45 | 285
599568 | Poziom 1K +5,45 | 116.002
599569 | Poziom 1K +5,45 | 113.5
599570 | Poziom 1K +5,45 | 285
599582 | Poziom 1K +5,45 | 113.5
599583 | Poziom 1K +5,45 | 113.5
599584 | Poziom 1K +5,45 | 285
599585 | Poziom 1K +5,45 | 285
599588 | Poziom 1K +5,45 | 113.5
599589 | Poziom 1K +5,45 | 118.5
599590 | Poziom 1K +5,45 | 285
599593 | Poziom 1K +5,45 | 118.5
599594 | Poziom 1K +5,45 | 113.5
599595 | Poziom 1K +5,45 | 285
599598 | Poziom 1K +5,45 | 113.5
599599 | Poziom 1K +5,45 | 116.002
599600 | Poziom 1K +5,45 | 285
599603 | Poziom 1K +5,45 | 116.002
599604 | Poziom 1K +5,45 | 113.5
599605 | Poziom 1K +5,45 | 285
599617 | Poziom 1K +5,45 | 113.5
599618 | Poziom 1K +5,45 | 113.5
599619 | Poziom 1K +5,45 | 285
599620 | Poziom 1K +5,45 | 285
599623 | Poziom 1K +5,45 | 113.5
599624 | Poziom 1K +5,45 | 118.5
599625 | Poziom 1K +5,45 | 285
599628 | Poziom 1K +5,45 | 118.5
599629 | Poziom 1K +5,45 | 113.5
599630 | Poziom 1K +5,45 | 285
599633 | Poziom 1K +5,45 | 113.5
599634 | Poziom 1K +5,45 | 116.002
599635 | Poziom 1K +5,45 | 285
599638 | Poziom 1K +5,45 | 116.002
599639 | Poziom 1K +5,45 | 113.5
599640 | Poziom 1K +5,45 | 285
599652 | Poziom 1K +5,45 | 113.5
599653 | Poziom 1K +5,45 | 113.5
599654 | Poziom 1K +5,45 | 285
599655 | Poziom 1K +5,45 | 285
599658 | Poziom 1K +5,45 | 113.5
599659 | Poziom 1K +5,45 | 118.5
599660 | Poziom 1K +5,45 | 285
599663 | Poziom 1K +5,45 | 118.5
599664 | Poziom 1K +5,45 | 113.5
599665 | Poziom 1K +5,45 | 285
599668 | Poziom 1K +5,45 | 113.5
599669 | Poziom 1K +5,45 | 116.002
599670 | Poziom 1K +5,45 | 285
599673 | Poziom 1K +5,45 | 116.002
599674 | Poziom 1K +5,45 | 113.5
599675 | Poziom 1K +5,45 | 285
599792 | Poziom 1K +5,45 | 118.5
599793 | Poziom 1K +5,45 | 123.5
599794 | Poziom 1K +5,45 | 285
599795 | Poziom 1K +5,45 | 280
600081 | Poziom 1K +5,45 | 118.5
600082 | Poziom 1K +5,45 | 116.002
600083 | Poziom 1K +5,45 | 285
600202 | Poziom 1K +5,45 | 116.002
600203 | Poziom 1K +5,45 | 116.002
600204 | Poziom 1K +5,45 | 285
600289 | Poziom 1K +5,45 | 116.002
600290 | Poziom 1K +5,45 | 116.002
600291 | Poziom 1K +5,45 | 285
600350 | Poziom 1K +5,45 | 116.002
600351 | Poziom 1K +5,45 | 116.002
600352 | Poziom 1K +5,45 | 285
600409 | Poziom 1K +5,45 | 116.002
600410 | Poziom 1K +5,45 | 118.5
600411 | Poziom 1K +5,45 | 285
601897 | Poziom 1K +5,45 | 129
601898 | Poziom 1K +5,45 | 129
601899 | Poziom 1K +5,45 | 285
601900 | Poziom 1K +5,45 | 285
602138 | Poziom 1K +5,45 | 129
602139 | Poziom 1K +5,45 | 129
602140 | Poziom 1K +5,45 | 285
627487 | Poziom 0 A +/-0,00 | 118.5
627488 | Poziom 0 A +/-0,00 | 113
627489 | Poziom 0 A +/-0,00 | 275
627490 | Poziom 0 A +/-0,00 | 275
627498 | Poziom 0 A +/-0,00 | 113
627499 | Poziom 0 A +/-0,00 | 118.5
643513 | Poziom 0 A +/-0,00 | 118.5
643514 | Poziom 0 A +/-0,00 | 116.002
643515 | Poziom 0 A +/-0,00 | 275
643516 | Poziom 0 A +/-0,00 | 275
643519 | Poziom 0 A +/-0,00 | 116.002
643520 | Poziom 0 A +/-0,00 | 118.5
643521 | Poziom 0 A +/-0,00 | 275
653769 | Poziom 1K +5,45 | 127
653770 | Poziom 1K +5,45 | 131
653771 | Poziom 1K +5,45 | 285
653772 | Poziom 1K +5,45 | 285
653778 | Poziom 1K +5,45 | 285
657612 | Poziom 1K +5,45 | 127
657632 | Poziom 1K +5,45 | 131

# IfcOpeningElement: Opening (263)
Name | In | Reference | sets with these values
Ściana podstawowa:Ściana żelbetowa gr. 25cm:449487 | Poziom 0K -0,10
Ściana podstawowa:Ściana żelbetowa gr. 25cm:406881 | Poziom 0K -0,10 | Otwór 235x95 | 2
Ściana podstawowa:Ściana żelbetowa gr. 25cm:406881 | Poziom 0K -0,10 | Otwór 130x250 | 2
Ściana podstawowa:Ściana żelbetowa gr. 25cm:407198 | Poziom 0K -0,10 | Otwór 238x155 | 2
2 x Ściana podstawowa:Ściana żelbetowa gr. 25cm:411803 | Poziom 0K -0,10 | Otwór 110x255 | 2
Ściana podstawowa:Ściana żelbetowa gr. 25cm:412574 | Poziom 0K -0,10 | Otwór 125x217,5 | 2
Ściana podstawowa:Ściana żelbetowa gr. 25cm:413153 | Poziom 0K -0,10 | Otwór 250x179 | 2
Ściana podstawowa:Ściana żelbetowa gr. 25cm:413153 | Poziom 0K -0,10 | Otwór 250x134 | 2
Strop:Płyta na gruncie gr. 30cm:419648:2 | Poziom 0K -0,10 | Płyta na gruncie gr. 30cm | 2
Strop:Płyta na gruncie gr. 30cm:419648:3 | Poziom 0K -0,10 | Płyta na gruncie gr. 30cm | 2
Strop:Strop żebetowy gr. 15cm:419794:2 | Poziom 1K +5,45 | Strop żebetowy gr. 15cm | 2
Strop:Strop żebetowy gr. 15cm:419794:3 | Poziom 1K +5,45 | Strop żebetowy gr. 15cm | 2
Strop:Strop żebetowy gr. 15cm:419794:4 | Poziom 1K +5,45 | Strop żebetowy gr. 15cm | 2
Strop:Strop żebetowy gr. 15cm:419794:5 | Poziom 1K +5,45 | Strop żebetowy gr. 15cm | 2
Strop:Strop żebetowy gr. 15cm:419794:6 | Poziom 1K +5,45 | Strop żebetowy gr. 15cm | 2
Strop:Strop żebetowy gr. 15cm:419794:7 | Poziom 1K +5,45 | Strop żebetowy gr. 15cm | 2
Strop:Strop żebetowy gr. 15cm:419794:8 | Poziom 1K +5,45 | Strop żebetowy gr. 15cm | 2
Strop:Strop żebetowy gr. 15cm:419794:9 | Poziom 1K +5,45 | Strop żebetowy gr. 15cm | 2
Strop:Strop żebetowy gr. 15cm:419794:10 | Poziom 1K +5,45 | Strop żebetowy gr. 15cm | 2
Strop:Strop żebetowy gr. 15cm:419794:11 | Poziom 1K +5,45 | Strop żebetowy gr. 15cm | 2
Strop:Strop żebetowy gr. 15cm:419794:12 | Poziom 1K +5,45 | Strop żebetowy gr. 15cm | 2
Strop:Strop żebetowy gr. 15cm:419794:13 | Poziom 1K +5,45 | Strop żebetowy gr. 15cm | 2
Strop:Strop żebetowy gr. 15cm:419794:14 | Poziom 1K +5,45 | Strop żebetowy gr. 15cm | 2
Strop:Strop żebetowy gr. 15cm:419794:15 | Poziom 1K +5,45 | Strop żebetowy gr. 15cm | 2
Strop:Strop żebetowy gr. 15cm:419794:16 | Poziom 1K +5,45 | Strop żebetowy gr. 15cm | 2
Strop:Strop żelbetowy gr. 35cm:420083:2 | Poziom 2K +9,70 | Strop żelbetowy gr. 35cm | 2
Strop:Strop żelbetowy gr. 35cm:420083:3 | Poziom 2K +9,70 | Strop żelbetowy gr. 35cm | 2
Strop:Strop żelbetowy gr. 35cm:420083:4 | Poziom 2K +9,70 | Strop żelbetowy gr. 35cm | 2
Strop:Strop żelbetowy gr. 35cm:420083:5 | Poziom 2K +9,70 | Strop żelbetowy gr. 35cm | 2
Strop:Strop żelbetowy gr. 35cm:420083:6 | Poziom 2K +9,70 | Strop żelbetowy gr. 35cm | 2
Strop:Strop żelbetowy gr. 35cm:420083:7 | Poziom 2K +9,70 | Strop żelbetowy gr. 35cm | 2
Strop:Strop żelbetowy gr. 35cm:420083:8 | Poziom 2K +9,70 | Strop żelbetowy gr. 35cm | 2
Strop:Strop żelbetowy gr. 35cm:420083:9 | Poziom 2K +9,70 | Strop żelbetowy gr. 35cm | 2
Strop:Strop żebetowy gr. 15cm:434339:2 | Poziom Antresola +2,90 | Strop żebetowy gr. 15cm | 2
Strop:Strop żebetowy gr. 15cm:434339:3 | Poziom Antresola +2,90 | Strop żebetowy gr. 15cm | 2
Strop:Strop żebetowy gr. 15cm:434339:4 | Poziom Antresola +2,90 | Strop żebetowy gr. 15cm | 2
Strop:Strop żebetowy gr. 15cm:434391:2 | Poziom 2K +9,70 | Strop żebetowy gr. 15cm | 2
2 x Ściana podstawowa:Ściana żelbetowa gr. 25cm:436775 | Poziom Antresola +2,90 | Otwór 70x140 | 2
Ściana podstawowa:Ściana żelbetowa gr. 25cm:444545 | Poziom 1K +5,45 | Otwór 125x217,5 | 2
Ściana podstawowa:Ściana żelbetowa gr. 25cm:449487 | Poziom 0K -0,10 | Otwór 105x210 | 2
Ściana podstawowa:Ściana żelbetowa gr. 25cm:473854 | Poziom Antresola +2,90 | Otwór 80x270 | 2
Ściana podstawowa:Ściana murowana bloczki silikatowegr. 15cm:476869 | Poziom 1K +5,45 | Otwór 120x230 | 2
Ściana podstawowa:Ściana murowana gr. 25cm:487229 | Poziom 0 A +/-0,00 | Otwór 122x210 | 2
Ściana podstawowa:Ściana żelbetowa gr. 25cm:488426 | Poziom 0K -0,10 | Otwór 313x210 | 2
3 x Ściana podstawowa:Ściana żelbetowa gr. 25cm:488426 | Poziom 0K -0,10 | Otwór 100x210 | 2
Ściana podstawowa:Ściana żelbetowa gr. 25cm:496793 | Poziom Antresola +2,90 | Otwór 210x80 | 2
Ściana podstawowa:Ściana żelbetowa gr. 25cm:499113 | Poziom 0K -0,10 | Otwór 197,5x265 | 2
Ściana podstawowa:Ściana GK rdzeń gr. 10cm:515271 | Poziom 1K +5,45 | Otwór 100x215 | 2
Ściana podstawowa:Ściana żelbetowa gr. 25cm:515745 | Poziom Antresola +2,90 | Otwór 155x210 | 2
3 x Ściana podstawowa:Ściana GK rdzeń gr. 10cm:518139 | Poziom 1K +5,45 | Otwór 100x215 | 2
Ściana podstawowa:Ściana GK rdzeń gr. 10cm:518142 | Poziom 1K +5,45 | Otwór 100x215 | 2
Ściana podstawowa:Ściana GK rdzeń gr. 10cm:522546 | Poziom 1K +5,45 | Otwór 100x215 | 2
Ściana podstawowa:Ściana GK rdzeń gr. 10cm:522607 | Poziom 1K +5,45 | Otwór 135x210 | 2
Ściana podstawowa:Ściana GK rdzeń gr. 10cm:522608 | Poziom 1K +5,45 | Otwór 135x210 | 2
2 x Ściana podstawowa:Ściana GK rdzeń gr. 10cm:522813 | Poziom 1K +5,45 | Otwór 100x215 | 2
Ściana podstawowa:Ściana GK rdzeń gr. 10cm:523168 | Poziom 1K +5,45 | Otwór 90x215 | 2
Ściana podstawowa:Ściana GK rdzeń gr. 10cm:523532 | Poziom 1K +5,45 | Otwór 100x215 | 2
Ściana podstawowa:Ściana GK rdzeń gr. 10cm:523783 | Poziom 1K +5,45 | Otwór 100x215 | 2
2 x Ściana podstawowa:Ściana GK rdzeń gr. 10cm:526137 | Poziom 1K +5,45 | Otwór 100x215 | 2
Ściana podstawowa:Ściana GK rdzeń gr. 10cm:526138 | Poziom 1K +5,45 | Otwór 100x215 | 2
Ściana podstawowa:Ściana GK rdzeń gr. 15cm:526140 | Poziom 1K +5,45 | Otwór 100x215 | 2
3 x Ściana podstawowa:Ściana GK rdzeń gr. 10cm:526143 | Poziom 1K +5,45 | Otwór 100x215 | 2
Ściana podstawowa:Ściana GK rdzeń gr. 10cm:526144 | Poziom 1K +5,45 | Otwór 100x215 | 2
Ściana podstawowa:Ściana GK rdzeń gr. 10cm:526145 | Poziom 1K +5,45 | Otwór 100x215 | 2
Ściana podstawowa:Ściana GK rdzeń gr. 10cm:526146 | Poziom 1K +5,45 | Otwór 90x215 | 2
Ściana podstawowa:Ściana żelbetowa gr. 25cm:533511 | Poziom Antresola +2,90 | Otwór 135x210 | 2
Ściana podstawowa:Ściana żelbetowa gr. 25cm:533511 | Poziom Antresola +2,90 | Otwór 155x210 | 2
Ściana podstawowa:Ściana żelbetowa gr. 25cm:534012 | Poziom 0K -0,10 | Otwór 450x385 | 2
Strop:Strop żebetowy gr. 15cm:534601:2 | Poziom Antresola +2,90 | Strop żebetowy gr. 15cm | 2
Strop:Strop żebetowy gr. 15cm:534601:3 | Poziom Antresola +2,90 | Strop żebetowy gr. 15cm | 2
Strop:Strop żebetowy gr. 15cm:534601:4 | Poziom Antresola +2,90 | Strop żebetowy gr. 15cm | 2
Ściana podstawowa:Ściana żelbetowa gr. 25cm:534626 | Poziom 0 A +/-0,00 | Otwór 197,5x265 | 2
Ściana podstawowa:Ściana żelbetowa gr. 25cm:534626 | Poziom 0 A +/-0,00 | Otwór 135x210 | 2
Ściana podstawowa:Ściana GK wykonczenie gr. 2,5cm:540046 | Poziom 1K +5,45 | Otwór 120x230 | 2
Ściana podstawowa:Ściana GK wykonczenie gr. 2,5cm:540046 | Poziom 1K +5,45 | Otwór 130x230 | 2
3 x Ściana podstawowa:Ściana GK wykonczenie gr. 2,5cm:552081 | Poziom 1K +5,45 | Otwór 100x215 | 2
Ściana podstawowa:Ściana GK wykonczenie gr. 2,5cm:552084 | Poziom 1K +5,45 | Otwór 100x215 | 2
Ściana podstawowa:Ściana GK wykonczenie gr. 2,5cm:552085 | Poziom 1K +5,45 | Otwór 100x215 | 2
Ściana podstawowa:Ściana GK wykonczenie gr. 2,5cm:552087 | Poziom 1K +5,45 | Otwór 100x215 | 2
Ściana podstawowa:Ściana GK wykonczenie gr. 2,5cm:552089 | Poziom 1K +5,45 | Otwór 100x215 | 2
Ściana podstawowa:Ściana GK wykonczenie gr. 2,5cm:552090 | Poziom 1K +5,45 | Otwór 100x215 | 2
Ściana podstawowa:Ściana GK wykonczenie gr. 2,5cm:552091 | Poziom 1K +5,45 | Otwór 100x215 | 2
Ściana podstawowa:Ściana GK wykonczenie gr. 2,5cm:552093 | Poziom 1K +5,45 | Otwór 90x215 | 2
Ściana podstawowa:Ściana GK wykonczenie gr. 2,5cm:552095 | Poziom 1K +5,45 | Otwór 90x215 | 2
Ściana podstawowa:Ściana GK wykonczenie gr. 2,5cm:552102 | Poziom 1K +5,45 | Otwór 100x215 | 2
2 x Ściana podstawowa:Ściana GK wykonczenie gr. 2,5cm:552115 | Poziom 1K +5,45 | Otwór 100x215 | 2
Ściana podstawowa:Ściana GK wykonczenie gr. 2,5cm:552455 | Poziom 1K +5,45 | Otwór 100x215 | 2
Ściana podstawowa:Ściana GK wykonczenie gr. 2,5cm:552484 | Poziom 1K +5,45 | Otwór 100x215 | 2
Ściana podstawowa:Ściana GK wykonczenie gr. 2,5cm:552867 | Poziom 1K +5,45 | Otwór 100x215 | 2
Ściana podstawowa:Ściana GK wykonczenie gr. 2,5cm:553058 | Poziom 1K +5,45 | Otwór 100x215 | 2
Ściana podstawowa:Ściana GK wykonczenie gr. 2,5cm:553149 | Poziom 1K +5,45 | Otwór 100x215 | 2
Ściana podstawowa:Ściana GK wykonczenie gr. 2,5cm:553534 | Poziom 1K +5,45 | Otwór 100x215 | 2
Ściana podstawowa:Ściana GK wykonczenie gr. 2,5cm:553626 | Poziom 1K +5,45 | Otwór 90x215 | 2
Ściana podstawowa:Ściana GK wykonczenie gr. 2,5cm:554023 | Poziom 1K +5,45 | Otwór 90x215 | 2
Ściana podstawowa:Ściana murowana bloczki silikatowegr. 15cm:554222 | Poziom 1K +5,45 | Otwór 130x230 | 2
Ściana podstawowa:Ściana GK wykonczenie gr. 2,5cm:554532 | Poziom 1K +5,45 | Otwór 100x215 | 2
2 x Ściana podstawowa:Ściana GK wykonczenie gr. 2,5cm:554626 | Poziom 1K +5,45 | Otwór 100x215 | 2
Ściana podstawowa:Ściana GK wykonczenie gr. 2,5cm:554747 | Poziom 1K +5,45 | Otwór 100x215 | 2
Ściana podstawowa:Ściana GK wykonczenie gr. 2,5cm:555252 | Poziom 1K +5,45 | Otwór 100x215 | 2
2 x Ściana podstawowa:Ściana GK wykonczenie gr. 2,5cm:555424 | Poziom 1K +5,45 | Otwór 100x215 | 2
Ściana podstawowa:Ściana GK wykonczenie gr. 2,5cm:555517 | Poziom 1K +5,45 | Otwór 100x215 | 2
Ściana podstawowa:Ściana murowana gr. 25cm:555753 | Poziom 1K +5,45 | Otwór 263x265 | 2
Ściana podstawowa:Ściana GK rdzeń gr. 10cm:555780 | Poziom 0 A +/-0,00 | Ściana GK otwor 1 | 2
Ściana podstawowa:Ściana GK rdzeń gr. 10cm:515258 | Poziom 0 A +/-0,00 | Ściana GK rdzeń gr. 10cm | 2
Ściana podstawowa:Ściana GK rdzeń gr. 15cm:555781 | Poziom 0 A +/-0,00 | Otwór 200x440 | 2
Ściana podstawowa:Ściana GK rdzeń gr. 15cm:555782 | Poziom 0 A +/-0,00 | Otwór 200x440 | 2
Ściana podstawowa:Ściana GK rdzeń gr. 15cm:555785 | Poziom 0 A +/-0,00 | Otwór 200x370 | 2
Ściana podstawowa:Ściana GK rdzeń gr. 15cm:555786 | Poziom 0 A +/-0,00 | Otwór 200x370 | 2
Ściana podstawowa:Ściana GK rdzeń gr. 10cm:555796 | Poziom 0 A +/-0,00 | Otwór 140x215 | 2
Ściana podstawowa:Ściana GK wykonczenie gr. 2,5cm:555844:1 | Poziom 1K +5,45 | Ściana GK wykonczenie gr. 2,5cm | 2
2 x Ściana podstawowa:Ściana GK wykonczenie gr. 2,5cm:555844 | Poziom 1K +5,45 | Otwór 135x210 | 2
Ściana podstawowa:Ściana GK wykonczenie gr. 2,5cm:556070 | Poziom 1K +5,45 | Otwór 100x215 | 2
Ściana podstawowa:Ściana GK wykonczenie gr. 2,5cm:556136 | Poziom 1K +5,45 | Otwór 100x215 | 2
Ściana podstawowa:Ściana GK wykonczenie gr. 2,5cm:557219 | Poziom 1K +5,45 | Otwór 100x215 | 2
Ściana podstawowa:Ściana GK wykonczenie gr. 2,5cm:558279 | Poziom 1K +5,45 | Otwór 100x215 | 2
Ściana podstawowa:Ściana GK wykonczenie gr. 2,5cm:558369 | Poziom 1K +5,45 | Otwór 100x215 | 2
Ściana podstawowa:Ściana GK wykonczenie gr. 2,5cm:558873 | Poziom 1K +5,45 | Otwór 100x215 | 2
Ściana podstawowa:Ściana GK wykonczenie gr. 2,5cm:559572 | Poziom 1K +5,45 | Otwór 100x215 | 2
Ściana podstawowa:Ściana GK wykonczenie gr. 2,5cm:568471 | Poziom 1K +5,45 | Otwór 135x210 | 2
Ściana podstawowa:Ściana GK wykonczenie gr. 2,5cm:570634 | Poziom 1K +5,45 | Otwór 100x215 | 2
Ściana podstawowa:Tynk wykończenie gr. 2,5cm:573283 | Poziom 0 A +/-0,00 | Otwór 122x210 | 2
Ściana podstawowa:Ściana GK wykonczenie gr. 2,5cm:574730 | Poziom 1K +5,45 | Otwór 120x230 | 2
Ściana podstawowa:Ściana GK wykonczenie gr. 2,5cm:574730 | Poziom 1K +5,45 | Otwór 130x230 | 2
Ściana podstawowa:Tynk wykończenie gr. 2,5cm:575594 | Poziom 0 A +/-0,00 | Otwór 313x210 | 2
3 x Ściana podstawowa:Tynk wykończenie gr. 2,5cm:575594 | Poziom 0 A +/-0,00 | Otwór 100x210 | 2
Ściana podstawowa:Tynk wykończenie gr. 2,5cm:575594 | Poziom 0 A +/-0,00 | Otwór 1975x2100mm | 2
Ściana podstawowa:Tynk wykończenie gr. 2,5cm:575594 | Poziom 0 A +/-0,00 | Otwór 105x210 | 2
Ściana podstawowa:Ściana GK wykonczenie gr. 2,5cm:577722 | Poziom 0 A +/-0,00 | Otwór 200x440 | 2
Ściana podstawowa:Ściana GK wykonczenie gr. 2,5cm:582322 | Poziom 0 A +/-0,00 | Otwór 200x440 | 2
Ściana podstawowa:Ściana GK wykonczenie gr. 2,5cm:582323 | Poziom 0 A +/-0,00 | Otwór 200x370 | 2
Ściana podstawowa:Ściana GK wykonczenie gr. 2,5cm:582324 | Poziom 0 A +/-0,00 | Otwór 200x370 | 2
Ściana podstawowa:Ściana GK wykonczenie gr. 2,5cm:582332 | Poziom 0 A +/-0,00 | Otwór 140x215 | 2
Ściana podstawowa:Ściana GK wykonczenie gr. 2,5cm:582339 | Poziom 0 A +/-0,00 | Otwór 200x370 | 2
Ściana podstawowa:Ściana GK wykonczenie gr. 2,5cm:582340 | Poziom 0 A +/-0,00 | Otwór 200x370 | 2
17 x Ściana podstawowa:Wełna mineralna gr. 20cm:636596 | Poziom 0 A +/-0,00 | Wełna mineralna gr. 20cm | 2
2 x Ściana podstawowa:Wełna mineralna gr. 20cm:593151 | Poziom 0 A +/-0,00 | SO2 | 2
Ściana podstawowa:Wełna mineralna gr. 20cm:593152 | Poziom 0 A +/-0,00 | Otwór 250x134 | 2
Ściana podstawowa:Wełna mineralna gr. 20cm:593152 | Poziom 0 A +/-0,00 | Otwór 250x179 | 2
12 x Ściana podstawowa:Wełna mineralna gr. 20cm:636596 | Poziom 1K +5,45 | Wełna mineralna gr. 20cm | 2
Ściana podstawowa:Wełna mineralna gr. 20cm:599453 | Poziom 1K +5,45 | Otwór 263x265 | 2
Strop:Wykładzina PCV komunikacja:604530:2 | Poziom 1K +5,45 | Wykładzina PCV komunikacja | 2
Strop:Wykładzina PCV komunikacja:604530:3 | Poziom 1K +5,45 | Wykładzina PCV komunikacja | 2
Strop:Stropodach - Polistyren ekstrudowany (XPS) 20cm:617756:2 | Poziom 2K +9,70 | Stropodach - Polistyren ekstrudowany (XPS) 20cm | 2
Strop:Stropodach - Polistyren ekstrudowany (XPS) 20cm:617756:3 | Poziom 2K +9,70 | Stropodach - Polistyren ekstrudowany (XPS) 20cm | 2
Strop:Stropodach - Polistyren ekstrudowany (XPS) 20cm:617756:4 | Poziom 2K +9,70 | Stropodach - Polistyren ekstrudowany (XPS) 20cm | 2
Strop:Stropodach - Polistyren ekstrudowany (XPS) 20cm:617756:5 | Poziom 2K +9,70 | Stropodach - Polistyren ekstrudowany (XPS) 20cm | 2
Strop:Stropodach - Polistyren ekstrudowany (XPS) 20cm:617756:6 | Poziom 2K +9,70 | Stropodach - Polistyren ekstrudowany (XPS) 20cm | 2
Strop:Stropodach - Polistyren ekstrudowany (XPS) 20cm:617756:7 | Poziom 2K +9,70 | Stropodach - Polistyren ekstrudowany (XPS) 20cm | 2
Strop:Stropodach - Polistyren ekstrudowany (XPS) 20cm:617756:8 | Poziom 2K +9,70 | Stropodach - Polistyren ekstrudowany (XPS) 20cm | 2
Strop:Stropodach - Polistyren ekstrudowany (XPS) 20cm:617756:9 | Poziom 2K +9,70 | Stropodach - Polistyren ekstrudowany (XPS) 20cm | 2
Ściana podstawowa:Ściana murowana gr. 15cm:620784 | Poziom 2K +9,70 | Otwór 120x40 | 2
Ściana podstawowa:Ściana murowana gr. 15cm:620784 | Poziom 2K +9,70 | Otwór 50x40 | 2
Strop:Płytki tarasowe gr. 4cm:627231:2 | Poziom 2K +9,70 | Płytki tarasowe gr. 4cm | 2
Strop:Płytki tarasowe gr. 4cm:627231:3 | Poziom 2K +9,70 | Płytki tarasowe gr. 4cm | 2
Strop:Płytki tarasowe gr. 4cm:627231:4 | Poziom 2K +9,70 | Płytki tarasowe gr. 4cm | 2
Strop:Płytki tarasowe gr. 4cm:627231:5 | Poziom 2K +9,70 | Płytki tarasowe gr. 4cm | 2
Strop:Płytki tarasowe gr. 4cm:627231:6 | Poziom 2K +9,70 | Płytki tarasowe gr. 4cm | 2
Strop:Płytki tarasowe gr. 4cm:627231:7 | Poziom 2K +9,70 | Płytki tarasowe gr. 4cm | 2
Strop:Płytki tarasowe gr. 4cm:627231:8 | Poziom 2K +9,70 | Płytki tarasowe gr. 4cm | 2
Strop:Płytki tarasowe gr. 4cm:627231:9 | Poziom 2K +9,70 | Płytki tarasowe gr. 4cm | 2
Strop:Płytki tarasowe gr. 4cm:627231:10 | Poziom 2K +9,70 | Płytki tarasowe gr. 4cm | 2
Strop:Płytki tarasowe gr. 4cm:627231:11 | Poziom 2K +9,70 | Płytki tarasowe gr. 4cm | 2
Strop:Opaska żwirowa gr. 8cm:627722:2 | Poziom 2K +9,70 | Opaska żwirowa gr. 8cm | 2
Ściana podstawowa:Ściana murowana gr. 15cm:635634 | Poziom 2K +9,70 | Otwór 80x40 | 2
Ściana podstawowa:Ściana murowana gr. 15cm:635636 | Poziom 2K +9,70 | Otwór 80x40 | 2
Strop:Wełna mineralna gr. 32 cm:636181:2 | Poziom 2K +9,70 | Wełna mineralna gr. 32 cm | 2
14 x Ściana podstawowa:Tynk zewnętrzny gr. 2cm:380258 | Poziom 1K +5,45 | Tynk zewnętrzny gr. 2cm | 2
8 x Ściana podstawowa:Tynk zewnętrzny gr. 2cm:380258 | Poziom 0 A +/-0,00 | Tynk zewnętrzny gr. 2cm | 2
Ściana podstawowa:Tynk zewnętrzny gr. 2cm:637896 | Poziom 0 A +/-0,00 | Otwór 250x179 | 2
Ściana podstawowa:Tynk zewnętrzny gr. 2cm:637896 | Poziom 0 A +/-0,00 | Otwór 250x134 | 2
Strop:Wełna mineralna gr. 10cm:640727:2 | Poziom 2K +9,70 | Wełna mineralna gr. 10cm | 2
4 x Ściana podstawowa:Wełna mineralna gr. 20cm:636596 | Poziom 2K +9,70 | Wełna mineralna gr. 20cm | 2
Obróbka komina 1:Obróbka komina 1:646959:1 | Poziom 2K +9,70 | Obróbka komina 1 | 2
Obróbka komina 2:Obróbka komina 2:653581:1 | Poziom 2K +9,70 | Obróbka komina 2 | 2
Ściana podstawowa:Ściana żelbetowa gr. 25cm:381402 | Poziom 1K +5,45 | Ściana żelbetowa gr. 25cm | 2
4 x Ściana podstawowa:Tynk zewnętrzny gr. 2cm:380258 | Poziom 2K +9,70 | Tynk zewnętrzny gr. 2cm | 2
Strop:Żywica epoksydowa pom. techniczne parter 2:681674:2 | Poziom Antresola +2,90 | Żywica epoksydowa pom. techniczne parter 2 | 2
Strop:Żywica epoksydowa pom. techniczne parter 2:681674:3 | Poziom Antresola +2,90 | Żywica epoksydowa pom. techniczne parter 2 | 2
Strop:Żywica epoksydowa pom. techniczne parter 2:681674:4 | Poziom Antresola +2,90 | Żywica epoksydowa pom. techniczne parter 2 | 2
Strop:Piasek gr. 4cm:684595:2 | Poziom 2K +9,70 | Piasek gr. 4cm | 2
Strop:Piasek gr. 4cm:684595:3 | Poziom 2K +9,70 | Piasek gr. 4cm | 2
Strop:Piasek gr. 4cm:684595:4 | Poziom 2K +9,70 | Piasek gr. 4cm | 2
Strop:Piasek gr. 4cm:684595:5 | Poziom 2K +9,70 | Piasek gr. 4cm | 2
Strop:Piasek gr. 4cm:684595:6 | Poziom 2K +9,70 | Piasek gr. 4cm | 2
Strop:Piasek gr. 4cm:684595:7 | Poziom 2K +9,70 | Piasek gr. 4cm | 2
Strop:Piasek gr. 4cm:684595:8 | Poziom 2K +9,70 | Piasek gr. 4cm | 2
Strop:Piasek gr. 4cm:684595:9 | Poziom 2K +9,70 | Piasek gr. 4cm | 2
Strop:Piasek gr. 4cm:684595:10 | Poziom 2K +9,70 | Piasek gr. 4cm | 2
Strop:Piasek gr. 4cm:684595:11 | Poziom 2K +9,70 | Piasek gr. 4cm | 2
Strop:Piasek gr. 8cm:684791:2 | Poziom 2K +9,70 | Piasek gr. 8cm | 2
Strop:Piasek gr. 8cm:684805:2 | Poziom 2K +9,70 | Piasek gr. 8cm | 2

# IfcPlate: Panel systemowy:Bryła (4)
In: Poziom Antresola +2,90
Type - PredefinedType: CURTAIN_PANEL; Material: Domyślny
Type - Pset_PlateCommon - IsExternal: no
Pset_PlateCommon - Reference: Bryła
Pset_QuantityTakeOff - Reference: Bryła
Name (Panel systemowy:Bryła:...)
602538
611652
611877
611885

# IfcPlate: Panel systemowy:Przeszklony (73)
Type - PredefinedType: CURTAIN_PANEL; Material: Szkło
Type - Pset_PlateCommon - IsExternal: no
Pset_PlateCommon - Reference: Przeszklony
Pset_QuantityTakeOff - Reference: Przeszklony
Name (Panel systemowy:Przeszklony:...) | In
540287 | Poziom 1K +5,45
557854 | Poziom 1K +5,45
557901 | Poziom 1K +5,45
584423 | Poziom 1K +5,45
557863 | Poziom 1K +5,45
557868 | Poziom 1K +5,45
557873 | Poziom 1K +5,45
557880 | Poziom 1K +5,45
585416 | Poziom 0 A +/-0,00
585717 | Poziom 0 A +/-0,00
586253 | Poziom 0 A +/-0,00
586427 | Poziom 0 A +/-0,00
586674 | Poziom 0 A +/-0,00
586808 | Poziom 0 A +/-0,00
586814 | Poziom 0 A +/-0,00
586819 | Poziom 0 A +/-0,00
586824 | Poziom 0 A +/-0,00
586829 | Poziom 0 A +/-0,00
586844 | Poziom 0 A +/-0,00
586850 | Poziom 0 A +/-0,00
586855 | Poziom 0 A +/-0,00
586860 | Poziom 0 A +/-0,00
586865 | Poziom 0 A +/-0,00
588401 | Poziom 0 A +/-0,00
589700 | Poziom 0 A +/-0,00
589933 | Poziom 0 A +/-0,00
590129 | Poziom 0 A +/-0,00
590304 | Poziom 0 A +/-0,00
591703 | Poziom 0 A +/-0,00
595278 | Poziom 0 A +/-0,00
595289 | Poziom 0 A +/-0,00
595300 | Poziom 0 A +/-0,00
595311 | Poziom 0 A +/-0,00
595325 | Poziom 0 A +/-0,00
597960 | Poziom 1K +5,45
598359 | Poziom 1K +5,45
598502 | Poziom 1K +5,45
598585 | Poziom 1K +5,45
598658 | Poziom 1K +5,45
599545 | Poziom 1K +5,45
599552 | Poziom 1K +5,45
599557 | Poziom 1K +5,45
599562 | Poziom 1K +5,45
599567 | Poziom 1K +5,45
599580 | Poziom 1K +5,45
599587 | Poziom 1K +5,45
599592 | Poziom 1K +5,45
599597 | Poziom 1K +5,45
599602 | Poziom 1K +5,45
599615 | Poziom 1K +5,45
599622 | Poziom 1K +5,45
599627 | Poziom 1K +5,45
599632 | Poziom 1K +5,45
599637 | Poziom 1K +5,45
599650 | Poziom 1K +5,45
599657 | Poziom 1K +5,45
599662 | Poziom 1K +5,45
599667 | Poziom 1K +5,45
599672 | Poziom 1K +5,45
599788 | Poziom 1K +5,45
600074 | Poziom 1K +5,45
600196 | Poziom 1K +5,45
600283 | Poziom 1K +5,45
600344 | Poziom 1K +5,45
600403 | Poziom 1K +5,45
601893 | Poziom 1K +5,45
602131 | Poziom 1K +5,45
627486 | Poziom 0 A +/-0,00
627497 | Poziom 0 A +/-0,00
643512 | Poziom 0 A +/-0,00
643518 | Poziom 0 A +/-0,00
653768 | Poziom 1K +5,45
653775 | Poziom 1K +5,45

# IfcPlate: Panel systemowy:Przeszklony - System strukturalny (25)
Type - PredefinedType: CURTAIN_PANEL; Material: Szkło
Type - Pset_PlateCommon - IsExternal: no
Pset_PlateCommon - Reference: Przeszklony - System strukturalny
Pset_QuantityTakeOff - Reference: Przeszklony - System strukturalny
Name (Panel systemowy:Przeszklony - System strukturalny:...) | In
611724 | Poziom Antresola +2,90
611713 | Poziom Antresola +2,90
611702 | Poziom Antresola +2,90
611694 | Poziom Antresola +2,90
611686 | Poziom Antresola +2,90
611675 | Poziom Antresola +2,90
611664 | Poziom Antresola +2,90
611878 | Poziom Antresola +2,90
611879 | Poziom Antresola +2,90
611880 | Poziom Antresola +2,90
611881 | Poziom Antresola +2,90
611882 | Poziom Antresola +2,90
611883 | Poziom Antresola +2,90
611884 | Poziom Antresola +2,90
613173 | Poziom 0 A +/-0,00
613215 | Poziom 0 A +/-0,00
613210 | Poziom 0 A +/-0,00
613205 | Poziom 0 A +/-0,00
613200 | Poziom 0 A +/-0,00
613195 | Poziom 0 A +/-0,00
613190 | Poziom 0 A +/-0,00
613185 | Poziom 0 A +/-0,00
613180 | Poziom 0 A +/-0,00
613323 | Poziom 0 A +/-0,00
613324 | Poziom 0 A +/-0,00

# IfcRailing: Poręcz:Rura 1100 SCK (5)
In: Poziom Antresola +2,90
Pset_QuantityTakeOff - Reference: Rura 1100 SCK
Pset_RailingCommon - IsExternal: no; Reference: Rura 1100 SCK; Height: 110 cm
Name (Poręcz:Rura 1100 SCK:...) | Material
659820 | <Unnamed> (11)
701216 | <Unnamed> (6)
701237 | <Unnamed> (22)
701257 | <Unnamed> (6)
702323 | <Unnamed> (6)

# IfcRoof: Obróbka attyki:Obróbka attyki, Obróbka attyki:Obróbka attyki:626937
In: Poziom 2K +9,70
Material: Blacha tytna cynk
Pset_QuantityTakeOff - Reference: Obróbka attyki
Pset_RoofCommon - IsExternal: yes; Reference: Obróbka attyki; TotalArea: 127.682 m2

# IfcRoof: Obróbka komina 1:Obróbka komina 1, Obróbka komina 1:Obróbka komina 1:646959
In: Poziom 2K +9,70
Material: Blacha tytna cynk
Pset_QuantityTakeOff - Reference: Obróbka komina 1
Pset_RoofCommon - IsExternal: yes; Reference: Obróbka komina 1; TotalArea: 3.09495 m2

# IfcRoof: Obróbka komina 2:Obróbka komina 2, Obróbka komina 2:Obróbka komina 2:653581
In: Poziom 2K +9,70
Material: Blacha tytna cynk
Pset_QuantityTakeOff - Reference: Obróbka komina 2
Pset_RoofCommon - IsExternal: yes; Reference: Obróbka komina 2; TotalArea: 4.33589 m2

# IfcRoof: obróbka nadszybia:obróbka nadszybia, obróbka nadszybia:obróbka nadszybia:639187
In: Poziom 2K +9,70
Material: Blacha tytna cynk
Pset_QuantityTakeOff - Reference: obróbka nadszybia
Pset_RoofCommon - IsExternal: yes; Reference: obróbka nadszybia; TotalArea: 12.831 m2

# IfcSlab: Głowica 1:Głowica 1, Głowica 1:Głowica 1:521096
In: Poziom 2K +9,70
Type - PredefinedType: FLOOR; Material: _Beton, C25/30
Type - Pset_SlabCommon - IsExternal: no
Pset_QuantityTakeOff - Reference: Głowica 1; sets with these values: 2
Pset_SlabCommon - Reference: Głowica 1

# IfcSlab: Głowica 2:Głowica 2, Głowica 2:Głowica 2:516432
In: Poziom 2K +9,70
Type - PredefinedType: FLOOR; Material: _Beton, C25/30
Type - Pset_SlabCommon - IsExternal: no
Pset_QuantityTakeOff - Reference: Głowica 2; sets with these values: 2
Pset_SlabCommon - Reference: Głowica 2

# IfcSlab: Głowica 3:Głowica 3, Głowica 3:Głowica 3:518138
In: Poziom 2K +9,70
Type - PredefinedType: FLOOR; Material: _Beton, C25/30
Type - Pset_SlabCommon - IsExternal: no
Pset_QuantityTakeOff - Reference: Głowica 3; sets with these values: 2
Pset_SlabCommon - Reference: Głowica 3

# IfcSlab: Głowica 4:Głowica 4, Głowica 4:Głowica 4:518005
In: Poziom 2K +9,70
Type - PredefinedType: FLOOR; Material: Domyślna powierzchnia
Type - Pset_SlabCommon - IsExternal: no
Pset_QuantityTakeOff - Reference: Głowica 4; sets with these values: 2
Pset_SlabCommon - Reference: Głowica 4

# IfcSlab: Głowica 5:Głowica 5, Głowica 5:Głowica 5:520617
In: Poziom 2K +9,70
Type - PredefinedType: FLOOR; Material: Domyślna powierzchnia
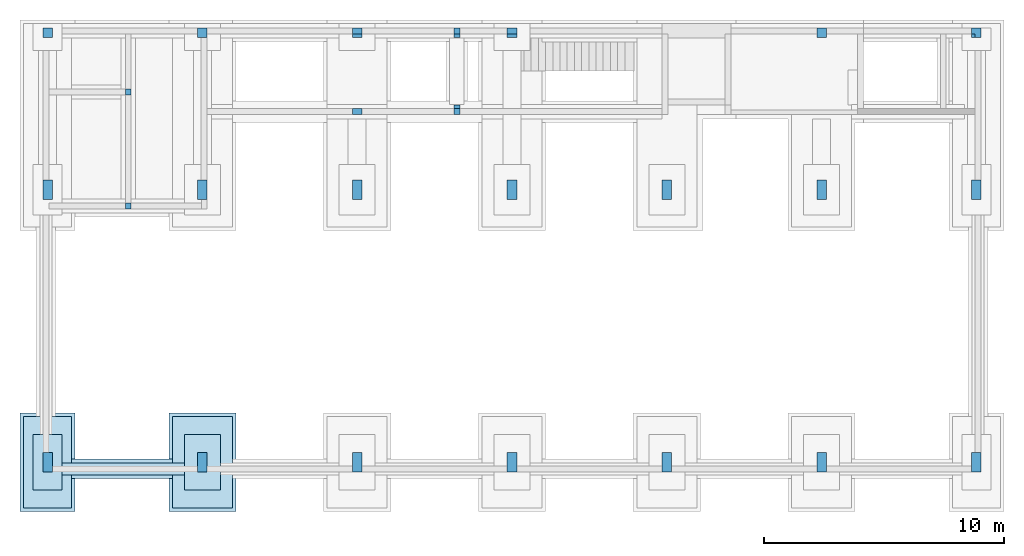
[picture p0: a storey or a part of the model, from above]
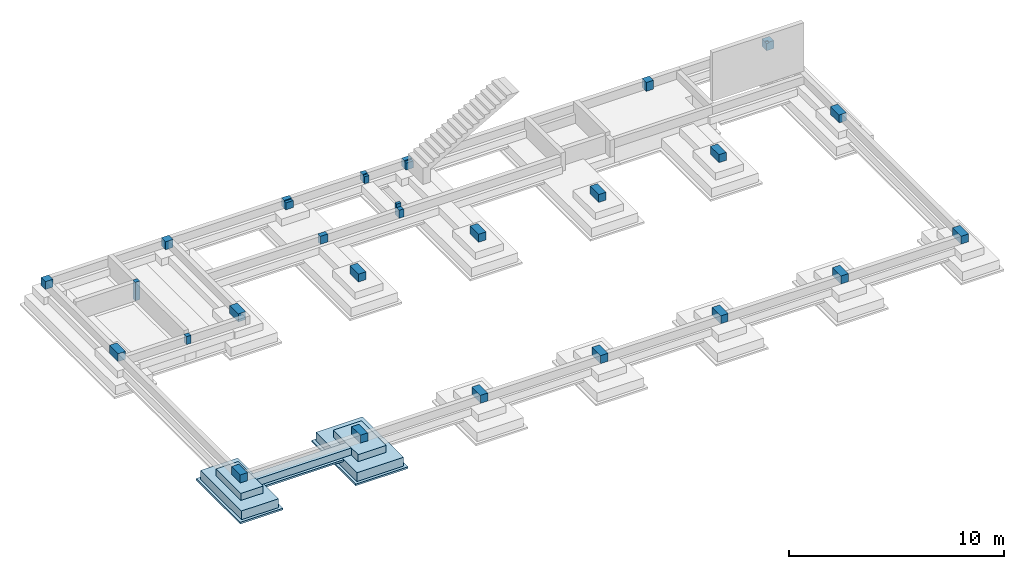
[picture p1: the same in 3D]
Properties of the parts of a building model (IFC2X3), part 2 of 2

# IfcSlab: Głowica 5:Głowica 5, Głowica 5:Głowica 5:520617
Type - Pset_SlabCommon - IsExternal: no
Pset_QuantityTakeOff - Reference: Głowica 5; sets with these values: 2
Pset_SlabCommon - Reference: Głowica 5

# IfcSlab: Obróbka komina 1:Obróbka komina 1, Obróbka komina 1:Obróbka komina 1:646959:1
In: Poziom 2K +9,70
Type - PredefinedType: ROOF
Type - Pset_SlabCommon - IsExternal: yes
Pset_QuantityTakeOff - Reference: Obróbka komina 1; sets with these values: 2
Pset_SlabCommon - Reference: Obróbka komina 1

# IfcSlab: Obróbka komina 2:Obróbka komina 2, Obróbka komina 2:Obróbka komina 2:653581:1
In: Poziom 2K +9,70
Type - PredefinedType: ROOF
Type - Pset_SlabCommon - IsExternal: yes
Pset_QuantityTakeOff - Reference: Obróbka komina 2; sets with these values: 2
Pset_SlabCommon - Reference: Obróbka komina 2

# IfcSlab: Strop:Chudy beton gr. 10cm (32)
In: Poziom Fundament -1,15
Type - PredefinedType: FLOOR; Material: Beton zacierany 10 cm
Type - Pset_SlabCommon - IsExternal: yes
Pset_QuantityTakeOff - Reference: Chudy beton gr. 10cm; sets with these values: 2
Pset_SlabCommon - LoadBearing: yes; PitchAngle: 0 deg; Reference: Chudy beton gr. 10cm
Name (Strop:Chudy beton gr. 10cm:...)
422844
422964
422991
423018
423045
423072
423099
423126
423153
423180
423207
423234
423261
423288
483341
483541
484631
485433
486463
495809
495826
495843
495861
499521
499541
499561
499578
499596
499613
499630
499647
499664

# IfcSlab: Strop:EPS 80 7 cm, Strop:EPS 80 7 cm:499681
In: Poziom 1K +5,45
Type - PredefinedType: FLOOR; Material: Styropian akustyczny 7 cm
Type - Pset_SlabCommon - IsExternal: no
Pset_QuantityTakeOff - Reference: EPS 80 7 cm; sets with these values: 2
Pset_SlabCommon - PitchAngle: 0 deg; Reference: EPS 80 7 cm; LoadBearing: no

# IfcSlab: Strop:Gres na kleju gr. 2cm (11)
Type - PredefinedType: FLOOR; Material: Gres 2 cm
Type - Pset_SlabCommon - IsExternal: yes; ThermalTransmittance: 60 kg/K/s3
Pset_QuantityTakeOff - Reference: Gres na kleju gr. 2cm; sets with these values: 2
Pset_SlabCommon - PitchAngle: 0 deg; LoadBearing: no; Reference: Gres na kleju gr. 2cm
Name (Strop:Gres na kleju gr. 2cm:...) | In
602961 | Poziom 1K +5,45
620791 | Poziom 0 A +/-0,00
680733 | Poziom 0 A +/-0,00
683585 | Poziom 1K +5,45
683659 | Poziom 1K +5,45
683733 | Poziom 1K +5,45
683806 | Poziom 1K +5,45
683879 | Poziom 1K +5,45
683953 | Poziom 1K +5,45
684029 | Poziom 1K +5,45
684106 | Poziom 1K +5,45

# IfcSlab: Strop:Gres na kleju gr. 2cm techniczne (9)
Type - PredefinedType: FLOOR; Material: Gres jasny 2 cm
Type - Pset_SlabCommon - IsExternal: yes; ThermalTransmittance: 60 kg/K/s3
Pset_QuantityTakeOff - Reference: Gres na kleju gr. 2cm techniczne; sets with these values: 2
Pset_SlabCommon - PitchAngle: 0 deg; LoadBearing: no; Reference: Gres na kleju gr. 2cm techniczne
Name (Strop:Gres na kleju gr. 2cm techniczne:...) | In
602946:2 | Poziom 1K +5,45
610505:4 | Poziom 0 A +/-0,00
680480 | Poziom 0 A +/-0,00
680523 | Poziom 0 A +/-0,00
680578:2 | Poziom 0 A +/-0,00
680627 | Poziom 0 A +/-0,00
680672 | Poziom 0 A +/-0,00
702605 | Poziom 0 A +/-0,00
702629 | Poziom 0 A +/-0,00

# IfcSlab: Strop:Gres na kleju gr. 2cm techniczne (5)
Type - PredefinedType: FLOOR
Type - Pset_SlabCommon - IsExternal: yes; ThermalTransmittance: 60 kg/K/s3
Material: Gres jasny 2 cm
Pset_QuantityTakeOff - Reference: Gres na kleju gr. 2cm techniczne; sets with these values: 2
Pset_SlabCommon - PitchAngle: 0 deg; LoadBearing: no; Reference: Gres na kleju gr. 2cm techniczne
Name (Strop:Gres na kleju gr. 2cm techniczne:...) | In
602946 | Poziom 1K +5,45
610505 | Poziom 0 A +/-0,00
610505:2 | Poziom 0 A +/-0,00
610505:3 | Poziom 0 A +/-0,00
680578 | Poziom 0 A +/-0,00

# IfcSlab: Strop:Krata pomostowa techniczna (7)
Type - PredefinedType: FLOOR; Material: _Metal krata pomostowa 4 cm
Type - Pset_SlabCommon - IsExternal: yes; ThermalTransmittance: 1125 kg/K/s3
Pset_QuantityTakeOff - Reference: Krata pomostowa techniczna; sets with these values: 2
Pset_SlabCommon - PitchAngle: 0 deg; Reference: Krata pomostowa techniczna
Name (Strop:Krata pomostowa techniczna:...) | In | LoadBearing
631602 | Poziom 0 A +/-0,00 | no
669431 | Poziom 2K +9,70 | yes
669902 | Poziom 2K +9,70 | yes
678595 | Poziom 0 A +/-0,00 | no
680445 | Poziom 0 A +/-0,00 | no
702234 | Poziom 2K +9,70 | yes
703174 | Poziom 2K +9,70 | yes

# IfcSlab: Strop:Opaska żwirowa gr. 8cm, Strop:Opaska żwirowa gr. 8cm:627722
In: Poziom 2K +9,70
Type - PredefinedType: FLOOR; Material: Opaska żwirowa 8 cm
Type - Pset_SlabCommon - IsExternal: yes; ThermalTransmittance: 4.5 kg/K/s3
Pset_QuantityTakeOff - Reference: Opaska żwirowa gr. 8cm; sets with these values: 2
Pset_SlabCommon - LoadBearing: yes; PitchAngle: 0 deg; Reference: Opaska żwirowa gr. 8cm

# IfcSlab: Strop:Piasek gr. 4cm, Strop:Piasek gr. 4cm:684595
In: Poziom 2K +9,70
Type - PredefinedType: FLOOR; Material: Piasek 4 cm
Type - Pset_SlabCommon - IsExternal: yes; ThermalTransmittance: 8.375 kg/K/s3
Pset_QuantityTakeOff - Reference: Piasek gr. 4cm; sets with these values: 2
Pset_SlabCommon - LoadBearing: yes; PitchAngle: 0 deg; Reference: Piasek gr. 4cm

# IfcSlab: Strop:Piasek gr. 8cm (12)
Type - PredefinedType: FLOOR; Material: Piasek 8 cm
Type - Pset_SlabCommon - IsExternal: yes; ThermalTransmittance: 4.1875 kg/K/s3
Pset_QuantityTakeOff - Reference: Piasek gr. 8cm; sets with these values: 2
Pset_SlabCommon - PitchAngle: 0 deg; LoadBearing: no; Reference: Piasek gr. 8cm
Name (Strop:Piasek gr. 8cm:...) | In
627407 | Poziom 2K +9,70
684295 | Poziom 0K -0,10
684325 | Poziom 0K -0,10
684353 | Poziom 0K -0,10
684381 | Poziom 0K -0,10
684416 | Poziom 0K -0,10
684444 | Poziom 0K -0,10
684472 | Poziom 0K -0,10
684500 | Poziom 0K -0,10
684529 | Poziom 0K -0,10
684791 | Poziom 2K +9,70
684805 | Poziom 2K +9,70

# IfcSlab: Strop:Podłoga podniesiona gr. 4cm (6)
In: Poziom 1K +5,45
Type - PredefinedType: FLOOR; Material: Panel płyty podłogowej 4 cm
Type - Pset_SlabCommon - IsExternal: no; ThermalTransmittance: 4.5 kg/K/s3
Pset_QuantityTakeOff - Reference: Podłoga podniesiona gr. 4cm; sets with these values: 2
Pset_SlabCommon - PitchAngle: 0 deg; LoadBearing: no; Reference: Podłoga podniesiona gr. 4cm
Name (Strop:Podłoga podniesiona gr. 4cm:...)
514060
514117
537109
540949
546262
546794

# IfcSlab: Strop:Podłoga techniczna z płyt pomostowych 3 cm (4)
Type - PredefinedType: FLOOR; Material: _Metal krata pomostowa 3 cm
Type - Pset_SlabCommon - IsExternal: no; ThermalTransmittance: 1500 kg/K/s3
Pset_QuantityTakeOff - Reference: Podłoga techniczna z płyt pomostowych 3 cm; sets with these values: 2
Pset_SlabCommon - PitchAngle: 0 deg; Reference: Podłoga techniczna z płyt pomostowych 3 cm
Name (Strop:Podłoga techniczna z płyt pomostowych 3 cm:...) | In | LoadBearing
547654 | Poziom 0 A +/-0,00 | no
547669 | Poziom 0 A +/-0,00 | no
547683 | Poziom 0 A +/-0,00 | no
597076 | Poziom Antresola +2,90 | yes

# IfcSlab: Strop:Powierzchnia utwardzona 1, Strop:Powierzchnia utwardzona 1:660301
In: Poziom 0 A +/-0,00
Type - PredefinedType: FLOOR; Material: Powierzchnia utwardzona 2 15 cm
Type - Pset_SlabCommon - IsExternal: no; ThermalTransmittance: 6.97333 kg/K/s3
Pset_QuantityTakeOff - Reference: Powierzchnia utwardzona 1; sets with these values: 2
Pset_SlabCommon - LoadBearing: yes; PitchAngle: 0 deg; Reference: Powierzchnia utwardzona 1

# IfcSlab: Strop:Powierzchnia utwardzona 2, Strop:Powierzchnia utwardzona 2:660414
In: Poziom 0 A +/-0,00
Type - PredefinedType: FLOOR; Material: Powierzchnia utwardzona 1 15 cm
Type - Pset_SlabCommon - IsExternal: no; ThermalTransmittance: 6.97333 kg/K/s3
Pset_QuantityTakeOff - Reference: Powierzchnia utwardzona 2; sets with these values: 2
Pset_SlabCommon - LoadBearing: yes; PitchAngle: 0 deg; Reference: Powierzchnia utwardzona 2

# IfcSlab: Strop:Płyta fundamentowa gr. 40cm (4)
In: Poziom Fundament -1,15
Type - PredefinedType: FLOOR; Material: _Beton, C25/30 40 cm
Type - Pset_SlabCommon - IsExternal: no; ThermalTransmittance: 2.615 kg/K/s3
Pset_QuantityTakeOff - Reference: Płyta fundamentowa gr. 40cm; sets with these values: 2
Pset_SlabCommon - LoadBearing: yes; PitchAngle: 0 deg; Reference: Płyta fundamentowa gr. 40cm
Name (Strop:Płyta fundamentowa gr. 40cm:...)
410628
481904
482517
482537

# IfcSlab: Strop:Płyta fundamentowa gr. 85cm, Strop:Płyta fundamentowa gr. 85cm:477515
In: Poziom Fundament -1,15
Type - PredefinedType: FLOOR
Type - Pset_SlabCommon - IsExternal: no; ThermalTransmittance: 1.23059 kg/K/s3
Material: _Beton, C25/30
Pset_QuantityTakeOff - Reference: Płyta fundamentowa gr. 85cm; sets with these values: 2
Pset_SlabCommon - LoadBearing: yes; PitchAngle: 0 deg; Reference: Płyta fundamentowa gr. 85cm

# IfcSlab: Strop:Płyta na gruncie gr. 25cm (2)
In: Poziom 0K -0,10
Type - PredefinedType: FLOOR; Material: _Beton, C25/30 25 cm
Type - Pset_SlabCommon - IsExternal: no; ThermalTransmittance: 4.184 kg/K/s3
Pset_QuantityTakeOff - Reference: Płyta na gruncie gr. 25cm; sets with these values: 2
Pset_SlabCommon - LoadBearing: yes; PitchAngle: 0 deg; Reference: Płyta na gruncie gr. 25cm
Name (Strop:Płyta na gruncie gr. 25cm:...)
509527
510757

# IfcSlab: Strop:Płyta na gruncie gr. 30cm, Strop:Płyta na gruncie gr. 30cm:419648
In: Poziom 0K -0,10
Type - PredefinedType: FLOOR; Material: _Beton, C25/30 30 cm
Type - Pset_SlabCommon - IsExternal: no; ThermalTransmittance: 3.48667 kg/K/s3
Pset_QuantityTakeOff - Reference: Płyta na gruncie gr. 30cm; sets with these values: 2
Pset_SlabCommon - LoadBearing: yes; PitchAngle: 0 deg; Reference: Płyta na gruncie gr. 30cm

# IfcSlab: Strop:Płytki tarasowe gr. 4cm, Strop:Płytki tarasowe gr. 4cm:627231
In: Poziom 2K +9,70
Type - PredefinedType: FLOOR; Material: Płytki tarasowe 4 cm
Type - Pset_SlabCommon - IsExternal: yes; ThermalTransmittance: 72.5 kg/K/s3
Pset_QuantityTakeOff - Reference: Płytki tarasowe gr. 4cm; sets with these values: 2
Pset_SlabCommon - LoadBearing: yes; PitchAngle: 0 deg; Reference: Płytki tarasowe gr. 4cm

# IfcSlab: Strop:Płyty betonowe gr. 12cm, Strop:Płyty betonowe gr. 12cm:532263
In: Poziom 0 A +/-0,00
Pset_QuantityTakeOff - Reference: Płyty betonowe gr. 12cm; sets with these values: 2
Pset_SlabCommon - IsExternal: yes; LoadBearing: no; Reference: Płyty betonowe gr. 12cm; ThermalTransmittance: 10.8333 kg/K/s3; PitchAngle: 1.0937 deg

# IfcSlab: Strop:Płyty betonowe gr. 12cm (2)
In: Poziom 0 A +/-0,00
Type - PredefinedType: FLOOR
Type - Pset_SlabCommon - IsExternal: yes; ThermalTransmittance: 10.8333 kg/K/s3
Material: Płyty betonowe 12 cm
Pset_QuantityTakeOff - Reference: Płyty betonowe gr. 12cm; sets with these values: 2
Pset_SlabCommon - LoadBearing: no; Reference: Płyty betonowe gr. 12cm; PitchAngle: 1.0937 deg

# IfcSlab: Strop:SF 112,5 x 120 x 40cm (2)
In: Poziom Fundament -1,15
Type - PredefinedType: FLOOR; Material: _Beton, C25/30 40 cm
Type - Pset_SlabCommon - IsExternal: no; ThermalTransmittance: 2.615 kg/K/s3
Pset_QuantityTakeOff - Reference: SF 112,5 x 120 x 40cm; sets with these values: 2
Pset_SlabCommon - LoadBearing: yes; PitchAngle: 0 deg; Reference: SF 112,5 x 120 x 40cm
Name (Strop:SF 112,5 x 120 x 40cm:...)
406970
411299

# IfcSlab: Strop:SF 120 x 210 x 40 cm (2)
In: Poziom Fundament -1,15
Type - PredefinedType: FLOOR; Material: _Beton, C25/30 40 cm
Type - Pset_SlabCommon - IsExternal: no; ThermalTransmittance: 2.615 kg/K/s3
Pset_QuantityTakeOff - Reference: SF 120 x 210 x 40 cm; sets with these values: 2
Pset_SlabCommon - LoadBearing: yes; PitchAngle: 0 deg; Reference: SF 120 x 210 x 40 cm
Name (Strop:SF 120 x 210 x 40 cm:...)
406925
410011

# IfcSlab: Strop:SF 120 x 230 x 40 cm (2)
In: Poziom Fundament -1,15
Type - PredefinedType: FLOOR; Material: _Beton, C25/30 40 cm
Type - Pset_SlabCommon - IsExternal: no; ThermalTransmittance: 2.615 kg/K/s3
Pset_QuantityTakeOff - Reference: SF 120 x 230 x 40 cm; sets with these values: 2
Pset_SlabCommon - LoadBearing: yes; PitchAngle: 0 deg; Reference: SF 120 x 230 x 40 cm
Name (Strop:SF 120 x 230 x 40 cm:...)
409347
409453

# IfcSlab: Strop:SF 150 x 210 x 40 cm (5)
In: Poziom Fundament -1,15
Type - PredefinedType: FLOOR; Material: _Beton, C25/30 40 cm
Type - Pset_SlabCommon - IsExternal: no; ThermalTransmittance: 2.615 kg/K/s3
Pset_QuantityTakeOff - Reference: SF 150 x 210 x 40 cm; sets with these values: 2
Pset_SlabCommon - LoadBearing: yes; PitchAngle: 0 deg; Reference: SF 150 x 210 x 40 cm
Name (Strop:SF 150 x 210 x 40 cm:...)
409638
409657
409674
409691
409985

# IfcSlab: Strop:SF 150 x 230 x 40 cm (5)
In: Poziom Fundament -1,15
Type - PredefinedType: FLOOR; Material: _Beton, C25/30 40 cm
Type - Pset_SlabCommon - IsExternal: no; ThermalTransmittance: 2.615 kg/K/s3
Pset_QuantityTakeOff - Reference: SF 150 x 230 x 40 cm; sets with these values: 2
Pset_SlabCommon - LoadBearing: yes; PitchAngle: 0 deg; Reference: SF 150 x 230 x 40 cm
Name (Strop:SF 150 x 230 x 40 cm:...)
409366
409385
409402
409419
409436

# IfcSlab: Strop:SF 200 x 380 x 50 cm (2)
In: Poziom Fundament -1,15
Type - PredefinedType: FLOOR; Material: _Beton, C25/30 50 cm
Type - Pset_SlabCommon - IsExternal: no; ThermalTransmittance: 2.092 kg/K/s3
Pset_QuantityTakeOff - Reference: SF 200 x 380 x 50 cm; sets with these values: 2
Pset_SlabCommon - LoadBearing: yes; PitchAngle: 0 deg; Reference: SF 200 x 380 x 50 cm
Name (Strop:SF 200 x 380 x 50 cm:...)
409311
409330

# IfcSlab: Strop:SF 200 x 847,5 x 50 cm (2)
In: Poziom Fundament -1,15
Type - PredefinedType: FLOOR; Material: _Beton, C25/30 50 cm
Type - Pset_SlabCommon - IsExternal: no; ThermalTransmittance: 2.092 kg/K/s3
Pset_QuantityTakeOff - Reference: SF 200 x 847,5 x 50 cm; sets with these values: 2
Pset_SlabCommon - LoadBearing: yes; Reference: SF 200 x 847,5 x 50 cm; PitchAngle: 0 deg
Name (Strop:SF 200 x 847,5 x 50 cm:...)
406903
407113

# IfcSlab: Strop:SF 250 x 380 x 50 cm (5)
In: Poziom Fundament -1,15
Type - PredefinedType: FLOOR; Material: _Beton, C25/30 50 cm
Type - Pset_SlabCommon - IsExternal: no; ThermalTransmittance: 2.092 kg/K/s3
Pset_QuantityTakeOff - Reference: SF 250 x 380 x 50 cm; sets with these values: 2
Pset_SlabCommon - LoadBearing: yes; PitchAngle: 0 deg; Reference: SF 250 x 380 x 50 cm
Name (Strop:SF 250 x 380 x 50 cm:...)
407130
407149
407166
407183
409528

# IfcSlab: Strop:SF 250 x 847,5 x 50 (5)
In: Poziom Fundament -1,15
Type - PredefinedType: FLOOR; Material: _Beton, C25/30 50 cm
Type - Pset_SlabCommon - IsExternal: no; ThermalTransmittance: 2.092 kg/K/s3
Pset_QuantityTakeOff - Reference: SF 250 x 847,5 x 50; sets with these values: 2
Pset_SlabCommon - LoadBearing: yes; PitchAngle: 0 deg; Reference: SF 250 x 847,5 x 50
Name (Strop:SF 250 x 847,5 x 50:...)
407009
407028
407045
407062
407079

# IfcSlab: Strop:SF 95 x 150 x 40cm (3)
In: Poziom Fundament -1,15
Type - PredefinedType: FLOOR; Material: _Beton, C25/30 40 cm
Type - Pset_SlabCommon - IsExternal: no; ThermalTransmittance: 2.615 kg/K/s3
Pset_QuantityTakeOff - Reference: SF 95 x 150 x 40cm; sets with these values: 2
Pset_SlabCommon - LoadBearing: yes; PitchAngle: 0 deg; Reference: SF 95 x 150 x 40cm
Name (Strop:SF 95 x 150 x 40cm:...)
411117
411190
411241

# IfcSlab: Strop:Spocznik gr. 15cm (2)
Type - PredefinedType: FLOOR; Material: _Beton, C25/30 15 cm
Type - Pset_SlabCommon - IsExternal: no; ThermalTransmittance: 6.97333 kg/K/s3
Pset_QuantityTakeOff - Reference: Spocznik gr. 15cm; sets with these values: 2
Pset_SlabCommon - LoadBearing: yes; PitchAngle: 0 deg; Reference: Spocznik gr. 15cm
Name (Strop:Spocznik gr. 15cm:...) | In
414518 | Poziom 0K -0,10
414557 | Poziom 1K +5,45

# IfcSlab: Strop:Strop gr. 10 cm (2)
In: Poziom 2K +9,70
Type - PredefinedType: FLOOR; Material: _Beton C30/37 10 cm
Type - Pset_SlabCommon - IsExternal: no; ThermalTransmittance: 10.46 kg/K/s3
Pset_QuantityTakeOff - Reference: Strop gr. 10 cm; sets with these values: 2
Pset_SlabCommon - LoadBearing: yes; PitchAngle: 0 deg; Reference: Strop gr. 10 cm
Name (Strop:Strop gr. 10 cm:...)
623820
635667

# IfcSlab: Strop:Strop żebetowy gr. 15cm (6)
Type - PredefinedType: FLOOR; Material: _Beton, C25/30 15 cm
Type - Pset_SlabCommon - IsExternal: no; ThermalTransmittance: 6.97333 kg/K/s3
Pset_QuantityTakeOff - Reference: Strop żebetowy gr. 15cm; sets with these values: 2
Pset_SlabCommon - LoadBearing: yes; PitchAngle: 0 deg; Reference: Strop żebetowy gr. 15cm
Name (Strop:Strop żebetowy gr. 15cm:...) | In
419794 | Poziom 1K +5,45
434339 | Poziom Antresola +2,90
434391 | Poziom 2K +9,70
534601 | Poziom Antresola +2,90
566848 | Poziom Antresola +2,90
641350 | Poziom Antresola +2,90

# IfcSlab: Strop:Strop żelbetowy gr. 20cm, Strop:Strop żelbetowy gr. 20cm:521420
In: Poziom 2K +9,70
Type - PredefinedType: FLOOR; Material: _Beton C30/37 20 cm
Type - Pset_SlabCommon - IsExternal: no; ThermalTransmittance: 5.23 kg/K/s3
Pset_QuantityTakeOff - Reference: Strop żelbetowy gr. 20cm; sets with these values: 2
Pset_SlabCommon - LoadBearing: yes; PitchAngle: 0 deg; Reference: Strop żelbetowy gr. 20cm

# IfcSlab: Strop:Strop żelbetowy gr. 35cm, Strop:Strop żelbetowy gr. 35cm:420083
In: Poziom 2K +9,70
Type - PredefinedType: FLOOR; Material: _Beton C30/37 35 cm
Type - Pset_SlabCommon - IsExternal: no; ThermalTransmittance: 2.98857 kg/K/s3
Pset_QuantityTakeOff - Reference: Strop żelbetowy gr. 35cm; sets with these values: 2
Pset_SlabCommon - LoadBearing: yes; PitchAngle: 0 deg; Reference: Strop żelbetowy gr. 35cm

# IfcSlab: Strop:Stropodach - Polistyren ekstrudowany (XPS) 10 cm, Strop:Stropodach - Polistyren ekstrudowany (XPS) 10 cm:623839
In: Poziom 2K +9,70
Type - PredefinedType: FLOOR; Material: Polistyren ekstrudowany (XPS) 10 cm
Type - Pset_SlabCommon - IsExternal: yes; ThermalTransmittance: 0.35 kg/K/s3
Pset_QuantityTakeOff - Reference: Stropodach - Polistyren ekstrudowany (XPS) 10 cm; sets with these values: 2
Pset_SlabCommon - PitchAngle: 0 deg; LoadBearing: no; Reference: Stropodach - Polistyren ekstrudowany (XPS) 10 cm

# IfcSlab: Strop:Stropodach - Polistyren ekstrudowany (XPS) 20cm, Strop:Stropodach - Polistyren ekstrudowany (XPS) 20cm:617756
In: Poziom 2K +9,70
Type - PredefinedType: FLOOR; Material: Polistyren ekstrudowany (XPS) 20 cm
Type - Pset_SlabCommon - IsExternal: yes; ThermalTransmittance: 0.175 kg/K/s3
Pset_QuantityTakeOff - Reference: Stropodach - Polistyren ekstrudowany (XPS) 20cm; sets with these values: 2
Pset_SlabCommon - PitchAngle: 0 deg; LoadBearing: no; Reference: Stropodach - Polistyren ekstrudowany (XPS) 20cm

# IfcSlab: Strop:Trawa, Strop:Trawa:660215
In: Poziom 0 A +/-0,00
Type - PredefinedType: FLOOR; Material: Trawa 15 cm
Type - Pset_SlabCommon - IsExternal: no
Pset_QuantityTakeOff - Reference: Trawa; sets with these values: 2
Pset_SlabCommon - LoadBearing: yes; PitchAngle: 0 deg; Reference: Trawa

# IfcSlab: Strop:Wełna mineralna gr. 10cm, Strop:Wełna mineralna gr. 10cm:640727
In: Poziom 2K +9,70
Type - PredefinedType: FLOOR; Material: Wełna skalna 10 cm
Type - Pset_SlabCommon - IsExternal: no; ThermalTransmittance: 5.02 kg/K/s3
Pset_QuantityTakeOff - Reference: Wełna mineralna gr. 10cm; sets with these values: 2
Pset_SlabCommon - PitchAngle: 0 deg; LoadBearing: no; Reference: Wełna mineralna gr. 10cm

# IfcSlab: Strop:Wełna mineralna gr. 20cm (4)
Type - PredefinedType: FLOOR; Material: Wełna skalna 20 cm
Type - Pset_SlabCommon - IsExternal: no; ThermalTransmittance: 2.51 kg/K/s3
Pset_QuantityTakeOff - Reference: Wełna mineralna gr. 20cm; sets with these values: 2
Pset_SlabCommon - PitchAngle: 0 deg; LoadBearing: no; Reference: Wełna mineralna gr. 20cm
Name (Strop:Wełna mineralna gr. 20cm:...) | In
644184 | Poziom 1K +5,45
645070 | Poziom 2K +9,70
645079 | Poziom 2K +9,70
647211 | Poziom 1K +5,45

# IfcSlab: Strop:Wełna mineralna gr. 32 cm, Strop:Wełna mineralna gr. 32 cm:636181
In: Poziom 2K +9,70
Type - PredefinedType: FLOOR; Material: Wełna skalna 32 cm
Type - Pset_SlabCommon - IsExternal: no; ThermalTransmittance: 1.56875 kg/K/s3
Pset_QuantityTakeOff - Reference: Wełna mineralna gr. 32 cm; sets with these values: 2
Pset_SlabCommon - LoadBearing: yes; PitchAngle: 0 deg; Reference: Wełna mineralna gr. 32 cm

# IfcSlab: Strop:Wykladzina winylowa (w plytkach) na kleju gr.2cm 2 (4)
Type - PredefinedType: FLOOR; Material: Wykladzina winylowa (w plytkach) na kleju 2 cm
Type - Pset_SlabCommon - IsExternal: yes
Pset_QuantityTakeOff - Reference: Wykladzina winylowa (w plytkach) na kleju gr.2cm 2; sets with these values: 2
Pset_SlabCommon - PitchAngle: 0 deg; LoadBearing: no; Reference: Wykladzina winylowa (w plytkach) na kleju gr.2cm 2
Name (Strop:Wykladzina winylowa (w plytkach) na kleju gr.2cm 2:...) | In
584335 | Poziom 1K +5,45
597061 | Poziom 1K +5,45
626985 | Poziom 0 A +/-0,00
682607 | Poziom 1K +5,45

# IfcSlab: Strop:Wykładzina PCV komunikacja, Strop:Wykładzina PCV komunikacja:604530
In: Poziom 1K +5,45
Type - PredefinedType: FLOOR; Material: wykladzina pcv 2 cm
Type - Pset_SlabCommon - IsExternal: yes; ThermalTransmittance: 60 kg/K/s3
Pset_QuantityTakeOff - Reference: Wykładzina PCV komunikacja; sets with these values: 2
Pset_SlabCommon - PitchAngle: 0 deg; LoadBearing: no; Reference: Wykładzina PCV komunikacja

# IfcSlab: Strop:Wylewka betonowa gr. 10cm (4)
In: Poziom 0 A +/-0,00
Type - PredefinedType: FLOOR; Material: Wylewka 10 cm
Type - Pset_SlabCommon - IsExternal: yes
Pset_QuantityTakeOff - Reference: Wylewka betonowa gr. 10cm; sets with these values: 2
Pset_SlabCommon - PitchAngle: 0 deg; LoadBearing: no; Reference: Wylewka betonowa gr. 10cm
Name (Strop:Wylewka betonowa gr. 10cm:...)
544785
544830
612961
681649

# IfcSlab: Strop:Wylewka betonowa gr. 6cm, Strop:Wylewka betonowa gr. 6cm:508368
In: Poziom 1K +5,45
Type - PredefinedType: FLOOR; Material: Wylewka 6 cm
Type - Pset_SlabCommon - IsExternal: yes
Pset_QuantityTakeOff - Reference: Wylewka betonowa gr. 6cm; sets with these values: 2
Pset_SlabCommon - PitchAngle: 0 deg; LoadBearing: no; Reference: Wylewka betonowa gr. 6cm

# IfcSlab: Strop:Wylewka zbrojona 8cm (2)
In: Poziom 0 A +/-0,00
Type - PredefinedType: FLOOR; Material: Wylewka 8 cm
Type - Pset_SlabCommon - IsExternal: no
Pset_QuantityTakeOff - Reference: Wylewka zbrojona 8cm; sets with these values: 2
Pset_SlabCommon - PitchAngle: 0 deg; LoadBearing: no; Reference: Wylewka zbrojona 8cm
Name (Strop:Wylewka zbrojona 8cm:...)
544801
544814

# IfcSlab: Strop:wełna mineralna twarda (dachowa), Strop:wełna mineralna twarda (dachowa):690585
In: Poziom 0 A +/-0,00
Type - PredefinedType: FLOOR; Material: Wełna mineralna (podłogowa) 25 cm
Type - Pset_SlabCommon - IsExternal: yes; ThermalTransmittance: 0.14 kg/K/s3
Pset_QuantityTakeOff - Reference: wełna mineralna twarda (dachowa); sets with these values: 2
Pset_SlabCommon - PitchAngle: 0 deg; LoadBearing: no; Reference: wełna mineralna twarda (dachowa)

# IfcSlab: Strop:ŁF 50 cm, Strop:ŁF 50 cm:477476
In: Poziom Fundament -1,15
Type - PredefinedType: FLOOR; Material: _Beton, C25/30 50 cm
Type - Pset_SlabCommon - IsExternal: no; ThermalTransmittance: 2.092 kg/K/s3
Pset_QuantityTakeOff - Reference: ŁF 50 cm; sets with these values: 2
Pset_SlabCommon - LoadBearing: yes; PitchAngle: 0 deg; Reference: ŁF 50 cm

# IfcSlab: Strop:Ława fundamentowa gr. 40cm (27)
In: Poziom Fundament -1,15
Type - PredefinedType: FLOOR; Material: _Beton, C25/30 40 cm
Type - Pset_SlabCommon - IsExternal: no; ThermalTransmittance: 2.615 kg/K/s3
Pset_QuantityTakeOff - Reference: Ława fundamentowa gr. 40cm; sets with these values: 2
Pset_SlabCommon - LoadBearing: yes; PitchAngle: 0 deg; Reference: Ława fundamentowa gr. 40cm
Name (Strop:Ława fundamentowa gr. 40cm:...)
406948
406989
410087
410365
410535
411349
411401
411446
411570
411685
411778
413657
413739
413905
414018
414044
414072
414102
414604
414974
415149
415248
415416
415478
415591
416972
416981

# IfcSlab: Strop:Żywica epoksydowa komunikacja parter, Strop:Żywica epoksydowa komunikacja parter:627013
In: Poziom 0 A +/-0,00
Type - PredefinedType: FLOOR; Material: Wylewka żywiczna 0.6 cm
Type - Pset_SlabCommon - IsExternal: yes; ThermalTransmittance: 83.6667 kg/K/s3
Pset_QuantityTakeOff - Reference: Żywica epoksydowa komunikacja parter; sets with these values: 2
Pset_SlabCommon - PitchAngle: 0 deg; LoadBearing: no; Reference: Żywica epoksydowa komunikacja parter

# IfcSlab: Strop:Żywica epoksydowa pom. techniczne parter 2 (8)
Type - PredefinedType: FLOOR; Material: Wylewka żywiczna szara 0.6 cm
Type - Pset_SlabCommon - IsExternal: yes; ThermalTransmittance: 83.6667 kg/K/s3
Pset_QuantityTakeOff - Reference: Żywica epoksydowa pom. techniczne parter 2; sets with these values: 2
Pset_SlabCommon - PitchAngle: 0 deg; LoadBearing: no; Reference: Żywica epoksydowa pom. techniczne parter 2
Name (Strop:Żywica epoksydowa pom. techniczne parter 2:...) | In
627795 | Poziom 0 A +/-0,00
632969 | Poziom Antresola +2,90
678122 | Poziom 0 A +/-0,00
678301 | Poziom 0 A +/-0,00
678453 | Poziom 0 A +/-0,00
678523 | Poziom 0 A +/-0,00
681674 | Poziom Antresola +2,90
681752 | Poziom Antresola +2,90

# IfcStair: Schody bieg1:Schody bieg1 (2)
In: Poziom Fundament -1,15
Name (Schody bieg1:Schody bieg1:...)
404140 | Material: _Beton, C25/30
404140 | Pset_QuantityTakeOff - Reference: Schody bieg1; Pset_StairCommon - IsExternal: no; Reference: Schody bieg1

# IfcStair: Schody bieg2:Schody bieg2 (2)
In: Poziom 0 A +/-0,00
Name (Schody bieg2:Schody bieg2:...)
406849 | Material: _Beton, C25/30
406849 | Pset_QuantityTakeOff - Reference: Schody bieg2; Pset_StairCommon - IsExternal: no; Reference: Schody bieg2

# IfcStair: Schody bieg3:Schody bieg3 (2)
In: Poziom Antresola +2,90
Name (Schody bieg3:Schody bieg3:...)
409090 | Material: _Beton, C25/30
409090 | Pset_QuantityTakeOff - Reference: Schody bieg3; Pset_StairCommon - IsExternal: no; Reference: Schody bieg3

# IfcStair: Schody stalowe zewnętrzne1:Schody stalowe zewnętrzne (2)
In: Poziom 1K +5,45
Name (Schody stalowe zewnętrzne1:Schody stalowe zewnętrzne:...)
702116 | Material: <Unnamed>
702116 | Pset_QuantityTakeOff - Reference: Schody stalowe zewnętrzne; Pset_StairCommon - IsExternal: no; Reference: Schody stalowe zewnętrzne

# IfcStair: Schody stalowe zewnętrzne:Schody stalowe zewnętrzne (2)
In: Poziom 1K +5,45
Name (Schody stalowe zewnętrzne:Schody stalowe zewnętrzne:...)
702056 | Material: <Unnamed>
702056 | Pset_QuantityTakeOff - Reference: Schody stalowe zewnętrzne; Pset_StairCommon - IsExternal: no; Reference: Schody stalowe zewnętrzne

# IfcWall: Ściana podstawowa:Tynk wykończenie gr. 2,5cm (7)
In: Poziom 1K +5,45
Type - PredefinedType: STANDARD; Material: Tynk gipsowy 2.5 cm
Type - Pset_WallCommon - IsExternal: yes; ThermalTransmittance: 26 kg/K/s3
Pset_QuantityTakeOff - Reference: Tynk wykończenie gr. 2,5cm; sets with these values: 2
Pset_WallCommon - ExtendToStructure: no; LoadBearing: no; Reference: Tynk wykończenie gr. 2,5cm
Name (Ściana podstawowa:Tynk wykończenie gr. 2,5cm:...)
552103
568463
568464
568465
568467
568469
568470

# IfcWall: Ściana podstawowa:Tynk zewnętrzny gr. 2cm (2)
In: Poziom 0 A +/-0,00
Type - PredefinedType: STANDARD; Material: Tynk gipsowy 2 cm
Type - Pset_WallCommon - IsExternal: yes; ThermalTransmittance: 32.5 kg/K/s3
Pset_QuantityTakeOff - Reference: Tynk zewnętrzny gr. 2cm; sets with these values: 2
Pset_WallCommon - ExtendToStructure: no; LoadBearing: no; Reference: Tynk zewnętrzny gr. 2cm
Name (Ściana podstawowa:Tynk zewnętrzny gr. 2cm:...)
637454
637570

# IfcWall: Ściana podstawowa:Wełna mineralna gr. 20cm, Ściana podstawowa:Wełna mineralna gr. 20cm:593150
In: Poziom 0 A +/-0,00
Type - PredefinedType: STANDARD; Material: Wełna skalna 20 cm
Type - Pset_WallCommon - IsExternal: yes; ThermalTransmittance: 2.51 kg/K/s3
Pset_QuantityTakeOff - Reference: Wełna mineralna gr. 20cm; sets with these values: 2
Pset_WallCommon - ExtendToStructure: no; LoadBearing: no; Reference: Wełna mineralna gr. 20cm

# IfcWall: Ściana podstawowa:Ściana GK wykonczenie gr. 2,5cm (9)
In: Poziom 1K +5,45
Type - PredefinedType: STANDARD; Material: Tynk gipsowy 2.5 cm
Type - Pset_WallCommon - IsExternal: yes; ThermalTransmittance: 26 kg/K/s3
Pset_QuantityTakeOff - Reference: Ściana GK wykonczenie gr. 2,5cm; sets with these values: 2
Pset_WallCommon - ExtendToStructure: no; LoadBearing: no; Reference: Ściana GK wykonczenie gr. 2,5cm
Name (Ściana podstawowa:Ściana GK wykonczenie gr. 2,5cm:...)
558466
558954
559699
568479
569249
569474
569598
572050
572258

# IfcWallStandardCase: Ściana podstawowa:Styropian XPS gr. 10cm (5)
In: Poziom 2K +9,70
Type - PredefinedType: STANDARD; Material: Polistyren XPS 10 cm
Type - Pset_WallCommon - IsExternal: yes
Pset_QuantityTakeOff - Reference: Styropian XPS gr. 10cm; sets with these values: 2
Pset_WallCommon - ExtendToStructure: no; LoadBearing: no; Reference: Styropian XPS gr. 10cm
Name (Ściana podstawowa:Styropian XPS gr. 10cm:...)
618617
618840
618988
619181
619582

# IfcWallStandardCase: Ściana podstawowa:Tynk wewnętrzny gr. 2cm (3)
In: Poziom 0 A +/-0,00
Type - PredefinedType: STANDARD; Material: Tynk gipsowy 2 cm
Type - Pset_WallCommon - IsExternal: yes; ThermalTransmittance: 32.5 kg/K/s3
Pset_QuantityTakeOff - Reference: Tynk wewnętrzny gr. 2cm; sets with these values: 2
Pset_WallCommon - ExtendToStructure: no; LoadBearing: no; Reference: Tynk wewnętrzny gr. 2cm
Name (Ściana podstawowa:Tynk wewnętrzny gr. 2cm:...)
682251
682379
683198

# IfcWallStandardCase: Ściana podstawowa:Tynk wykończenie gr. 2,5cm (62)
Type - PredefinedType: STANDARD; Material: Tynk gipsowy 2.5 cm
Type - Pset_WallCommon - IsExternal: yes; ThermalTransmittance: 26 kg/K/s3
Pset_QuantityTakeOff - Reference: Tynk wykończenie gr. 2,5cm; sets with these values: 2
Pset_WallCommon - ExtendToStructure: no; LoadBearing: no; Reference: Tynk wykończenie gr. 2,5cm
Name (Ściana podstawowa:Tynk wykończenie gr. 2,5cm:...) | In
552082 | Poziom 1K +5,45
552104 | Poziom 1K +5,45
552105 | Poziom 1K +5,45
552106 | Poziom 1K +5,45
552107 | Poziom 1K +5,45
552108 | Poziom 1K +5,45
566613 | Poziom 0 A +/-0,00
566665 | Poziom 0 A +/-0,00
568466 | Poziom 1K +5,45
568468 | Poziom 1K +5,45
573282 | Poziom 0 A +/-0,00
573283 | Poziom 0 A +/-0,00
573288 | Poziom 0 A +/-0,00
573289 | Poziom 0 A +/-0,00
573290 | Poziom 0 A +/-0,00
573291 | Poziom 0 A +/-0,00
573292 | Poziom 0 A +/-0,00
573293 | Poziom 0 A +/-0,00
573294 | Poziom 0 A +/-0,00
573297 | Poziom 0 A +/-0,00
573298 | Poziom 0 A +/-0,00
573299 | Poziom 0 A +/-0,00
573300 | Poziom 0 A +/-0,00
573301 | Poziom 0 A +/-0,00
573302 | Poziom 0 A +/-0,00
573303 | Poziom 0 A +/-0,00
573304 | Poziom 0 A +/-0,00
573305 | Poziom 0 A +/-0,00
573306 | Poziom 0 A +/-0,00
573307 | Poziom 0 A +/-0,00
573918 | Poziom 0 A +/-0,00
573919 | Poziom 0 A +/-0,00
573920 | Poziom 0 A +/-0,00
573921 | Poziom 0 A +/-0,00
573922 | Poziom 0 A +/-0,00
573923 | Poziom 0 A +/-0,00
573924 | Poziom 0 A +/-0,00
573925 | Poziom 0 A +/-0,00
573926 | Poziom 0 A +/-0,00
573927 | Poziom 0 A +/-0,00
574037 | Poziom 0 A +/-0,00
574082 | Poziom 0 A +/-0,00
574158 | Poziom 0 A +/-0,00
574233 | Poziom 0 A +/-0,00
574535 | Poziom 0 A +/-0,00
575591 | Poziom 0 A +/-0,00
575592 | Poziom 0 A +/-0,00
575594 | Poziom 0 A +/-0,00
575595 | Poziom 0 A +/-0,00
575596 | Poziom 0 A +/-0,00
576962 | Poziom 0 A +/-0,00
577117 | Poziom 0 A +/-0,00
577252 | Poziom 0 A +/-0,00
577401 | Poziom 0 A +/-0,00
577433 | Poziom 0 A +/-0,00
577517 | Poziom 0 A +/-0,00
582318 | Poziom 0 A +/-0,00
582319 | Poziom 0 A +/-0,00
582320 | Poziom 0 A +/-0,00
582321 | Poziom 0 A +/-0,00
582341 | Poziom 0 A +/-0,00
589380 | Poziom 0 A +/-0,00

# IfcWallStandardCase: Ściana podstawowa:Tynk zewnętrzny gr. 2cm (22)
Type - PredefinedType: STANDARD; Material: Tynk gipsowy 2 cm
Type - Pset_WallCommon - IsExternal: yes; ThermalTransmittance: 32.5 kg/K/s3
Pset_QuantityTakeOff - Reference: Tynk zewnętrzny gr. 2cm; sets with these values: 2
Pset_WallCommon - ExtendToStructure: no; LoadBearing: no; Reference: Tynk zewnętrzny gr. 2cm
Name (Ściana podstawowa:Tynk zewnętrzny gr. 2cm:...) | In
637432 | Poziom 1K +5,45
637543 | Poziom 1K +5,45
637598 | Poziom 1K +5,45
637753 | Poziom 0 A +/-0,00
637896 | Poziom 0 A +/-0,00
637927 | Poziom 1K +5,45
638114 | Poziom 2K +9,70
638264 | Poziom 2K +9,70
638402 | Poziom 2K +9,70
679607 | Poziom 2K +9,70
685026 | Poziom 2K +9,70
685263 | Poziom 2K +9,70
685480 | Poziom 2K +9,70
685481 | Poziom 2K +9,70
685573 | Poziom 2K +9,70
685654 | Poziom 2K +9,70
686366 | Poziom 2K +9,70
687130 | Poziom Antresola +2,90
687234 | Poziom Antresola +2,90
687308 | Poziom Antresola +2,90
687363 | Poziom Antresola +2,90
687458 | Poziom Antresola +2,90

# IfcWallStandardCase: Ściana podstawowa:Wełna mineralna gr. 10cm (4)
In: Poziom 2K +9,70
Type - PredefinedType: STANDARD; Material: Wełna skalna 10 cm
Type - Pset_WallCommon - IsExternal: yes; ThermalTransmittance: 5.02 kg/K/s3
Pset_QuantityTakeOff - Reference: Wełna mineralna gr. 10cm; sets with these values: 2
Pset_WallCommon - ExtendToStructure: no; LoadBearing: no; Reference: Wełna mineralna gr. 10cm
Name (Ściana podstawowa:Wełna mineralna gr. 10cm:...)
636496
637060
637133
637246

# IfcWallStandardCase: Ściana podstawowa:Wełna mineralna gr. 15cm (6)
Type - PredefinedType: STANDARD; Material: Wełna skalna 15 cm
Type - Pset_WallCommon - IsExternal: yes; ThermalTransmittance: 3.34667 kg/K/s3
Pset_QuantityTakeOff - Reference: Wełna mineralna gr. 15cm; sets with these values: 2
Pset_WallCommon - ExtendToStructure: no; LoadBearing: no; Reference: Wełna mineralna gr. 15cm
Name (Ściana podstawowa:Wełna mineralna gr. 15cm:...) | In
618191 | Poziom 1K +5,45
619744 | Poziom 1K +5,45
619746 | Poziom 0 A +/-0,00
619954 | Poziom 0 A +/-0,00
627630 | Poziom 1K +5,45
627688 | Poziom 0 A +/-0,00

# IfcWallStandardCase: Ściana podstawowa:Wełna mineralna gr. 20cm (22)
Type - PredefinedType: STANDARD; Material: Wełna skalna 20 cm
Type - Pset_WallCommon - IsExternal: yes; ThermalTransmittance: 2.51 kg/K/s3
Pset_QuantityTakeOff - Reference: Wełna mineralna gr. 20cm; sets with these values: 2
Pset_WallCommon - ExtendToStructure: no; LoadBearing: no; Reference: Wełna mineralna gr. 20cm
Name (Ściana podstawowa:Wełna mineralna gr. 20cm:...) | In
593148 | Poziom 0 A +/-0,00
593151 | Poziom 0 A +/-0,00
593152 | Poziom 0 A +/-0,00
599450 | Poziom 1K +5,45
599451 | Poziom 1K +5,45
599452 | Poziom 1K +5,45
599453 | Poziom 1K +5,45
619258 | Poziom 2K +9,70
619357 | Poziom 2K +9,70
619466 | Poziom 2K +9,70
643577 | Poziom 0 A +/-0,00
643580 | Poziom 0 A +/-0,00
644985 | Poziom 2K +9,70
644986 | Poziom 2K +9,70
644987 | Poziom 2K +9,70
644988 | Poziom 2K +9,70
645036 | Poziom 2K +9,70
645037 | Poziom 2K +9,70
645038 | Poziom 2K +9,70
645039 | Poziom 2K +9,70
647231 | Poziom 1K +5,45
663852 | Poziom 2K +9,70

# IfcWallStandardCase: Ściana podstawowa:Ściana GK rdzeń gr. 10cm (31)
Type - PredefinedType: STANDARD; Material: Wełna skalna 10 cm
Type - Pset_WallCommon - IsExternal: yes; ThermalTransmittance: 5.02 kg/K/s3
Pset_QuantityTakeOff - Reference: Ściana GK rdzeń gr. 10cm; sets with these values: 2
Pset_WallCommon - ExtendToStructure: no; LoadBearing: no; Reference: Ściana GK rdzeń gr. 10cm
Name (Ściana podstawowa:Ściana GK rdzeń gr. 10cm:...) | In
515260 | Poziom 1K +5,45
515271 | Poziom 1K +5,45
518139 | Poziom 1K +5,45
518140 | Poziom 1K +5,45
518141 | Poziom 1K +5,45
518142 | Poziom 1K +5,45
522415 | Poziom 1K +5,45
522546 | Poziom 1K +5,45
522607 | Poziom 1K +5,45
522608 | Poziom 1K +5,45
522609 | Poziom 1K +5,45
522610 | Poziom 1K +5,45
522813 | Poziom 1K +5,45
523168 | Poziom 1K +5,45
523532 | Poziom 1K +5,45
523783 | Poziom 1K +5,45
524019 | Poziom 1K +5,45
526137 | Poziom 1K +5,45
526138 | Poziom 1K +5,45
526139 | Poziom 1K +5,45
526143 | Poziom 1K +5,45
526144 | Poziom 1K +5,45
526145 | Poziom 1K +5,45
526146 | Poziom 1K +5,45
526147 | Poziom 1K +5,45
527128 | Poziom 1K +5,45
544698 | Poziom 1K +5,45
555778 | Poziom 0 A +/-0,00
555779 | Poziom 0 A +/-0,00
555780 | Poziom 0 A +/-0,00
555796 | Poziom 0 A +/-0,00

# IfcWallStandardCase: Ściana podstawowa:Ściana GK rdzeń gr. 15cm (8)
Type - PredefinedType: STANDARD; Material: Wełna skalna 15 cm
Type - Pset_WallCommon - IsExternal: yes; ThermalTransmittance: 3.34667 kg/K/s3
Pset_QuantityTakeOff - Reference: Ściana GK rdzeń gr. 15cm; sets with these values: 2
Pset_WallCommon - ExtendToStructure: no; LoadBearing: no; Reference: Ściana GK rdzeń gr. 15cm
Name (Ściana podstawowa:Ściana GK rdzeń gr. 15cm:...) | In
522611 | Poziom 1K +5,45
526140 | Poziom 1K +5,45
555781 | Poziom 0 A +/-0,00
555782 | Poziom 0 A +/-0,00
555783 | Poziom 0 A +/-0,00
555784 | Poziom 0 A +/-0,00
555785 | Poziom 0 A +/-0,00
555786 | Poziom 0 A +/-0,00

# IfcWallStandardCase: Ściana podstawowa:Ściana GK rdzeń gr. 5cm (61)
Type - PredefinedType: STANDARD; Material: Wełna skalna 5 cm
Type - Pset_WallCommon - IsExternal: yes; ThermalTransmittance: 10.04 kg/K/s3
Pset_QuantityTakeOff - Reference: Ściana GK rdzeń gr. 5cm; sets with these values: 2
Pset_WallCommon - ExtendToStructure: no; LoadBearing: no; Reference: Ściana GK rdzeń gr. 5cm
Name (Ściana podstawowa:Ściana GK rdzeń gr. 5cm:...) | In
524460 | Poziom 1K +5,45
524668 | Poziom 1K +5,45
524801 | Poziom 1K +5,45
526265 | Poziom 1K +5,45
526396 | Poziom 1K +5,45
526561 | Poziom 1K +5,45
526885 | Poziom 1K +5,45
536243 | Poziom 1K +5,45
536505 | Poziom 1K +5,45
536691 | Poziom 1K +5,45
536753 | Poziom 1K +5,45
536879 | Poziom 1K +5,45
543973 | Poziom 1K +5,45
543974 | Poziom 1K +5,45
543975 | Poziom 1K +5,45
543977 | Poziom 1K +5,45
543979 | Poziom 1K +5,45
543981 | Poziom 1K +5,45
544031 | Poziom 1K +5,45
544032 | Poziom 1K +5,45
544033 | Poziom 1K +5,45
544034 | Poziom 1K +5,45
544265 | Poziom 1K +5,45
544266 | Poziom 1K +5,45
544267 | Poziom 1K +5,45
544268 | Poziom 1K +5,45
544629 | Poziom 1K +5,45
544630 | Poziom 1K +5,45
544631 | Poziom 1K +5,45
544632 | Poziom 1K +5,45
544963 | Poziom 1K +5,45
544964 | Poziom 1K +5,45
545020 | Poziom 1K +5,45
545057 | Poziom 1K +5,45
545396 | Poziom 1K +5,45
545397 | Poziom 1K +5,45
545636 | Poziom 1K +5,45
545666 | Poziom 1K +5,45
545941 | Poziom 1K +5,45
545978 | Poziom 1K +5,45
548248 | Poziom 1K +5,45
548249 | Poziom 1K +5,45
548250 | Poziom 1K +5,45
548251 | Poziom 1K +5,45
548393 | Poziom 1K +5,45
548465 | Poziom 1K +5,45
548549 | Poziom 1K +5,45
548608 | Poziom 1K +5,45
555774 | Poziom 0 A +/-0,00
555775 | Poziom 0 A +/-0,00
555776 | Poziom 0 A +/-0,00
555777 | Poziom 0 A +/-0,00
555801 | Poziom 0 A +/-0,00
555802 | Poziom 0 A +/-0,00
555803 | Poziom 0 A +/-0,00
555805 | Poziom 0 A +/-0,00
555806 | Poziom 0 A +/-0,00
555807 | Poziom 0 A +/-0,00
555808 | Poziom 0 A +/-0,00
557494 | Poziom 1K +5,45
557527 | Poziom 1K +5,45

# IfcWallStandardCase: Ściana podstawowa:Ściana GK wykonczenie gr. 2,5cm (146)
Type - PredefinedType: STANDARD; Material: Tynk gipsowy 2.5 cm
Type - Pset_WallCommon - IsExternal: yes; ThermalTransmittance: 26 kg/K/s3
Pset_QuantityTakeOff - Reference: Ściana GK wykonczenie gr. 2,5cm; sets with these values: 2
Pset_WallCommon - ExtendToStructure: no; LoadBearing: no; Reference: Ściana GK wykonczenie gr. 2,5cm
Name (Ściana podstawowa:Ściana GK wykonczenie gr. 2,5cm:...) | In
540046 | Poziom 1K +5,45
540116 | Poziom 1K +5,45
552081 | Poziom 1K +5,45
552083 | Poziom 1K +5,45
552084 | Poziom 1K +5,45
552085 | Poziom 1K +5,45
552087 | Poziom 1K +5,45
552088 | Poziom 1K +5,45
552089 | Poziom 1K +5,45
552090 | Poziom 1K +5,45
552091 | Poziom 1K +5,45
552092 | Poziom 1K +5,45
552093 | Poziom 1K +5,45
552094 | Poziom 1K +5,45
552095 | Poziom 1K +5,45
552096 | Poziom 1K +5,45
552097 | Poziom 1K +5,45
552098 | Poziom 1K +5,45
552099 | Poziom 1K +5,45
552100 | Poziom 1K +5,45
552101 | Poziom 1K +5,45
552102 | Poziom 1K +5,45
552115 | Poziom 1K +5,45
552314 | Poziom 1K +5,45
552398 | Poziom 1K +5,45
552455 | Poziom 1K +5,45
552484 | Poziom 1K +5,45
552553 | Poziom 1K +5,45
552867 | Poziom 1K +5,45
553058 | Poziom 1K +5,45
553149 | Poziom 1K +5,45
553194 | Poziom 1K +5,45
553534 | Poziom 1K +5,45
553567 | Poziom 1K +5,45
553626 | Poziom 1K +5,45
553654 | Poziom 1K +5,45
554023 | Poziom 1K +5,45
554055 | Poziom 1K +5,45
554227 | Poziom 1K +5,45
554454 | Poziom 1K +5,45
554532 | Poziom 1K +5,45
554626 | Poziom 1K +5,45
554747 | Poziom 1K +5,45
554866 | Poziom 1K +5,45
555105 | Poziom 1K +5,45
555252 | Poziom 1K +5,45
555424 | Poziom 1K +5,45
555517 | Poziom 1K +5,45
555633 | Poziom 1K +5,45
555809 | Poziom 0 A +/-0,00
555810 | Poziom 0 A +/-0,00
555811 | Poziom 0 A +/-0,00
555812 | Poziom 0 A +/-0,00
555813 | Poziom 0 A +/-0,00
555814 | Poziom 0 A +/-0,00
555815 | Poziom 0 A +/-0,00
555844 | Poziom 1K +5,45
555975 | Poziom 1K +5,45
556015 | Poziom 1K +5,45
556070 | Poziom 1K +5,45
556136 | Poziom 1K +5,45
556157 | Poziom 1K +5,45
556213 | Poziom 1K +5,45
556665 | Poziom 1K +5,45
556687 | Poziom 1K +5,45
556770 | Poziom 1K +5,45
556811 | Poziom 1K +5,45
557099 | Poziom 1K +5,45
557219 | Poziom 1K +5,45
557295 | Poziom 1K +5,45
557365 | Poziom 1K +5,45
557398 | Poziom 1K +5,45
557836 | Poziom 0 A +/-0,00
558168 | Poziom 1K +5,45
558279 | Poziom 1K +5,45
558369 | Poziom 1K +5,45
558433 | Poziom 1K +5,45
558583 | Poziom 1K +5,45
558873 | Poziom 1K +5,45
558926 | Poziom 1K +5,45
558978 | Poziom 1K +5,45
559026 | Poziom 1K +5,45
559097 | Poziom 1K +5,45
559464 | Poziom 1K +5,45
559495 | Poziom 1K +5,45
559572 | Poziom 1K +5,45
559595 | Poziom 1K +5,45
559623 | Poziom 1K +5,45
559763 | Poziom 1K +5,45
559793 | Poziom 1K +5,45
559877 | Poziom 1K +5,45
560840 | Poziom 1K +5,45
560867 | Poziom 1K +5,45
560913 | Poziom 1K +5,45
560937 | Poziom 1K +5,45
568471 | Poziom 1K +5,45
568472 | Poziom 1K +5,45
568474 | Poziom 1K +5,45
568475 | Poziom 1K +5,45
568476 | Poziom 1K +5,45
568477 | Poziom 1K +5,45
568478 | Poziom 1K +5,45
568480 | Poziom 1K +5,45
568964 | Poziom 1K +5,45
568987 | Poziom 1K +5,45
569144 | Poziom 1K +5,45
569353 | Poziom 1K +5,45
569547 | Poziom 1K +5,45
569687 | Poziom 1K +5,45
569715 | Poziom 1K +5,45
569807 | Poziom 1K +5,45
570373 | Poziom 1K +5,45
570404 | Poziom 1K +5,45
570513 | Poziom 1K +5,45
570634 | Poziom 1K +5,45
570674 | Poziom 1K +5,45
570816 | Poziom 1K +5,45
570936 | Poziom 1K +5,45
570957 | Poziom 1K +5,45
571029 | Poziom 1K +5,45
571756 | Poziom 1K +5,45
571906 | Poziom 1K +5,45
571952 | Poziom 1K +5,45
572169 | Poziom 1K +5,45
574730 | Poziom 1K +5,45
575364 | Poziom 1K +5,45
577722 | Poziom 0 A +/-0,00
582314 | Poziom 0 A +/-0,00
582317 | Poziom 0 A +/-0,00
582322 | Poziom 0 A +/-0,00
582323 | Poziom 0 A +/-0,00
582324 | Poziom 0 A +/-0,00
582326 | Poziom 0 A +/-0,00
582327 | Poziom 0 A +/-0,00
582328 | Poziom 0 A +/-0,00
582329 | Poziom 0 A +/-0,00
582330 | Poziom 0 A +/-0,00
582331 | Poziom 0 A +/-0,00
582332 | Poziom 0 A +/-0,00
582333 | Poziom 0 A +/-0,00
582334 | Poziom 0 A +/-0,00
582335 | Poziom 0 A +/-0,00
582336 | Poziom 0 A +/-0,00
582337 | Poziom 0 A +/-0,00
582339 | Poziom 0 A +/-0,00
582340 | Poziom 0 A +/-0,00

# IfcWallStandardCase: Ściana podstawowa:Ściana daszku gr. 10cm (4)
In: Poziom 0 A +/-0,00
Type - PredefinedType: STANDARD; Material: _Beton C30/37 10 cm
Type - Pset_WallCommon - IsExternal: yes; ThermalTransmittance: 10.46 kg/K/s3
Pset_QuantityTakeOff - Reference: Ściana daszku gr. 10cm; sets with these values: 2
Pset_WallCommon - ExtendToStructure: no; LoadBearing: no; Reference: Ściana daszku gr. 10cm
Name (Ściana podstawowa:Ściana daszku gr. 10cm:...)
537888
537889
537890
537891

# IfcWallStandardCase: Ściana podstawowa:Ściana fundamentowa - 20,5cm, Ściana podstawowa:Ściana fundamentowa - 20,5cm:418658
In: Poziom Fundament -1,15
Type - PredefinedType: STANDARD; Material: _Beton, C25/30 20.5 cm
Type - Pset_WallCommon - IsExternal: yes; ThermalTransmittance: 5.10244 kg/K/s3
Pset_QuantityTakeOff - Reference: Ściana fundamentowa - 20,5cm; sets with these values: 2
Pset_WallCommon - ExtendToStructure: no; LoadBearing: yes; Reference: Ściana fundamentowa - 20,5cm

# IfcWallStandardCase: Ściana podstawowa:Ściana fundamentowa - 24cm (8)
In: Poziom Fundament -1,15
Type - PredefinedType: STANDARD; Material: _Beton, C25/30 24 cm
Type - Pset_WallCommon - IsExternal: yes; ThermalTransmittance: 4.35833 kg/K/s3
Pset_QuantityTakeOff - Reference: Ściana fundamentowa - 24cm; sets with these values: 2
Pset_WallCommon - ExtendToStructure: no; LoadBearing: yes; Reference: Ściana fundamentowa - 24cm
Name (Ściana podstawowa:Ściana fundamentowa - 24cm:...)
399831
400237
413533
413535
413537
414234
414373
414802

# IfcWallStandardCase: Ściana podstawowa:Ściana fundamentowa gr. 25cm (26)
In: Poziom Fundament -1,15
Type - PredefinedType: STANDARD; Material: _Beton, C25/30 25 cm
Type - Pset_WallCommon - ThermalTransmittance: 4.184 kg/K/s3; IsExternal: yes
Pset_QuantityTakeOff - Reference: Ściana fundamentowa gr. 25cm; sets with these values: 2
Pset_WallCommon - Reference: Ściana fundamentowa gr. 25cm; ExtendToStructure: no; LoadBearing: yes
Name (Ściana podstawowa:Ściana fundamentowa gr. 25cm:...)
379964
401432
409468
409471
409473
409475
409477
409479
413529
413531
413547
416988
417038
417078
417248
417351
417465
417635
417716
417854
417988
418397
418441
419260
479873
480129

# IfcWallStandardCase: Ściana podstawowa:Ściana murowana bloczki silikatowegr. 15cm (6)
In: Poziom 1K +5,45
Type - PredefinedType: STANDARD; Material: Pustak silikatowy 15 cm
Type - Pset_WallCommon - IsExternal: yes; ThermalTransmittance: 3.6 kg/K/s3
Pset_QuantityTakeOff - Reference: Ściana murowana bloczki silikatowegr. 15cm; sets with these values: 2
Pset_WallCommon - ExtendToStructure: no; Reference: Ściana murowana bloczki silikatowegr. 15cm
Name (Ściana podstawowa:Ściana murowana bloczki silikatowegr. 15cm:...) | LoadBearing
475294 | yes
476427 | yes
476596 | yes
476653 | yes
476869 | yes
554222 | no

# IfcWallStandardCase: Ściana podstawowa:Ściana murowana gr. 15cm (9)
Type - PredefinedType: STANDARD; Material: Pustak ceramiczny, klasa 15 15 cm
Type - Pset_WallCommon - IsExternal: yes; ThermalTransmittance: 3.6 kg/K/s3
Pset_QuantityTakeOff - Reference: Ściana murowana gr. 15cm; sets with these values: 2
Pset_WallCommon - ExtendToStructure: no; Reference: Ściana murowana gr. 15cm
Name (Ściana podstawowa:Ściana murowana gr. 15cm:...) | In | LoadBearing
521054 | Poziom 0 A +/-0,00 | yes
620781 | Poziom 2K +9,70 | no
620782 | Poziom 2K +9,70 | no
620783 | Poziom 2K +9,70 | no
620784 | Poziom 2K +9,70 | no
635633 | Poziom 2K +9,70 | no
635634 | Poziom 2K +9,70 | no
635635 | Poziom 2K +9,70 | no
635636 | Poziom 2K +9,70 | no

# IfcWallStandardCase: Ściana podstawowa:Ściana murowana gr. 25cm (35)
Type - PredefinedType: STANDARD; Material: Pustak ceramiczny, klasa 15 25 cm
Type - Pset_WallCommon - IsExternal: yes; ThermalTransmittance: 2.16 kg/K/s3
Pset_QuantityTakeOff - Reference: Ściana murowana gr. 25cm; sets with these values: 2
Pset_WallCommon - ExtendToStructure: no; LoadBearing: yes; Reference: Ściana murowana gr. 25cm
Name (Ściana podstawowa:Ściana murowana gr. 25cm:...) | In
440861 | Poziom 0K -0,10
441132 | Poziom 0K -0,10
441553 | Poziom 0K -0,10
441918 | Poziom 0K -0,10
442117 | Poziom 0K -0,10
442438 | Poziom 0K -0,10
442777 | Poziom 0K -0,10
446108 | Poziom 1K +5,45
446256 | Poziom 1K +5,45
449758 | Poziom 1K +5,45
450062 | Poziom 1K +5,45
450297 | Poziom 1K +5,45
450457 | Poziom 1K +5,45
450675 | Poziom 1K +5,45
450847 | Poziom 1K +5,45
451113 | Poziom 1K +5,45
451293 | Poziom 1K +5,45
477397 | Poziom 0 A +/-0,00
477427 | Poziom 0K -0,10
477437 | Poziom 0K -0,10
477447 | Poziom 0K -0,10
487229 | Poziom 0 A +/-0,00
508554 | Poziom 0 A +/-0,00
508564 | Poziom 0 A +/-0,00
542702 | Poziom 0K -0,10
555753 | Poziom 1K +5,45
562090 | Poziom Antresola +2,90
562517 | Poziom Antresola +2,90
567736 | Poziom 1K +5,45
568055 | Poziom 0K -0,10
588915 | Poziom 0K -0,10
592337 | Poziom 0K -0,10
593779 | Poziom 0K -0,10
601086 | Poziom 1K +5,45
704078 | Poziom Antresola +2,90

# IfcWallStandardCase: Ściana podstawowa:Ściana murowana gr. 40cm, Ściana podstawowa:Ściana murowana gr. 40cm:483896
In: Poziom 0 A +/-0,00
Type - PredefinedType: STANDARD; Material: Cegła, zwykła 40 cm
Type - Pset_WallCommon - IsExternal: yes; ThermalTransmittance: 1.35 kg/K/s3
Pset_QuantityTakeOff - Reference: Ściana murowana gr. 40cm; sets with these values: 2
Pset_WallCommon - ExtendToStructure: no; LoadBearing: yes; Reference: Ściana murowana gr. 40cm

# IfcWallStandardCase: Ściana podstawowa:Ściana żelbetowa gr. 20cm (6)
In: Poziom 2K +9,70
Type - PredefinedType: STANDARD; Material: _Beton C30/37 20 cm
Type - Pset_WallCommon - IsExternal: yes; ThermalTransmittance: 5.23 kg/K/s3
Pset_QuantityTakeOff - Reference: Ściana żelbetowa gr. 20cm; sets with these values: 2
Pset_WallCommon - ExtendToStructure: no; LoadBearing: yes; Reference: Ściana żelbetowa gr. 20cm
Name (Ściana podstawowa:Ściana żelbetowa gr. 20cm:...)
458371
458693
459602
459870
460182
702872

# IfcWallStandardCase: Ściana podstawowa:Ściana żelbetowa gr. 25cm (60)
Type - PredefinedType: STANDARD; Material: _Beton C30/37 25 cm
Type - Pset_WallCommon - IsExternal: yes; ThermalTransmittance: 4.184 kg/K/s3
Pset_QuantityTakeOff - Reference: Ściana żelbetowa gr. 25cm; sets with these values: 2
Pset_WallCommon - ExtendToStructure: no; Reference: Ściana żelbetowa gr. 25cm
Name (Ściana podstawowa:Ściana żelbetowa gr. 25cm:...) | In | LoadBearing
406881 | Poziom 0K -0,10 | yes
406891 | Poziom 0K -0,10 | yes
407198 | Poziom 0K -0,10 | yes
411803 | Poziom 0K -0,10 | yes
411813 | Poziom 0K -0,10 | yes
412313 | Poziom 0K -0,10 | yes
412574 | Poziom 0K -0,10 | yes
412712 | Poziom 0K -0,10 | yes
413153 | Poziom 0K -0,10 | yes
413422 | Poziom 0K -0,10 | yes
415625 | Poziom 0 A +/-0,00 | yes
421978 | Poziom 0K -0,10 | yes
423315 | Poziom 0K -0,10 | yes
423325 | Poziom 0K -0,10 | yes
423419 | Poziom 0K -0,10 | yes
434409 | Poziom 2K +9,70 | yes
434429 | Poziom 2K +9,70 | yes
436775 | Poziom Antresola +2,90 | yes
444354 | Poziom 1K +5,45 | yes
444545 | Poziom 1K +5,45 | yes
445033 | Poziom 1K +5,45 | yes
445421 | Poziom 1K +5,45 | yes
446521 | Poziom 1K +5,45 | yes
448030 | Poziom 1K +5,45 | yes
448093 | Poziom 1K +5,45 | yes
448218 | Poziom 1K +5,45 | yes
448279 | Poziom 1K +5,45 | yes
449487 | Poziom 0K -0,10 | yes
451888 | Poziom 1K +5,45 | yes
452032 | Poziom 1K +5,45 | yes
452659 | Poziom 1K +5,45 | yes
452738 | Poziom 1K +5,45 | yes
473854 | Poziom Antresola +2,90 | yes
473961 | Poziom Antresola +2,90 | yes
488426 | Poziom 0K -0,10 | yes
488784 | Poziom 0K -0,10 | yes
496791 | Poziom Antresola +2,90 | yes
496793 | Poziom Antresola +2,90 | yes
498787 | Poziom Fundament -1,15 | yes
499113 | Poziom 0K -0,10 | yes
508574 | Poziom 0K -0,10 | yes
515743 | Poziom Antresola +2,90 | yes
515745 | Poziom Antresola +2,90 | yes
533511 | Poziom Antresola +2,90 | yes
534012 | Poziom 0K -0,10 | yes
534626 | Poziom 0 A +/-0,00 | yes
567646 | Poziom 1K +5,45 | yes
567955 | Poziom 0K -0,10 | yes
609596 | Poziom 1K +5,45 | yes
635682 | Poziom 2K +9,70 | no
635683 | Poziom 2K +9,70 | no
635684 | Poziom 2K +9,70 | no
635685 | Poziom 2K +9,70 | no
635812 | Poziom 2K +9,70 | yes
653745 | Poziom 0K -0,10 | yes
653747 | Poziom 0 A +/-0,00 | yes
653750 | Poziom Antresola +2,90 | yes
654078 | Poziom Antresola +2,90 | yes
660176 | Poziom 1K +5,45 | no
660195 | Poziom 1K +5,45 | no
